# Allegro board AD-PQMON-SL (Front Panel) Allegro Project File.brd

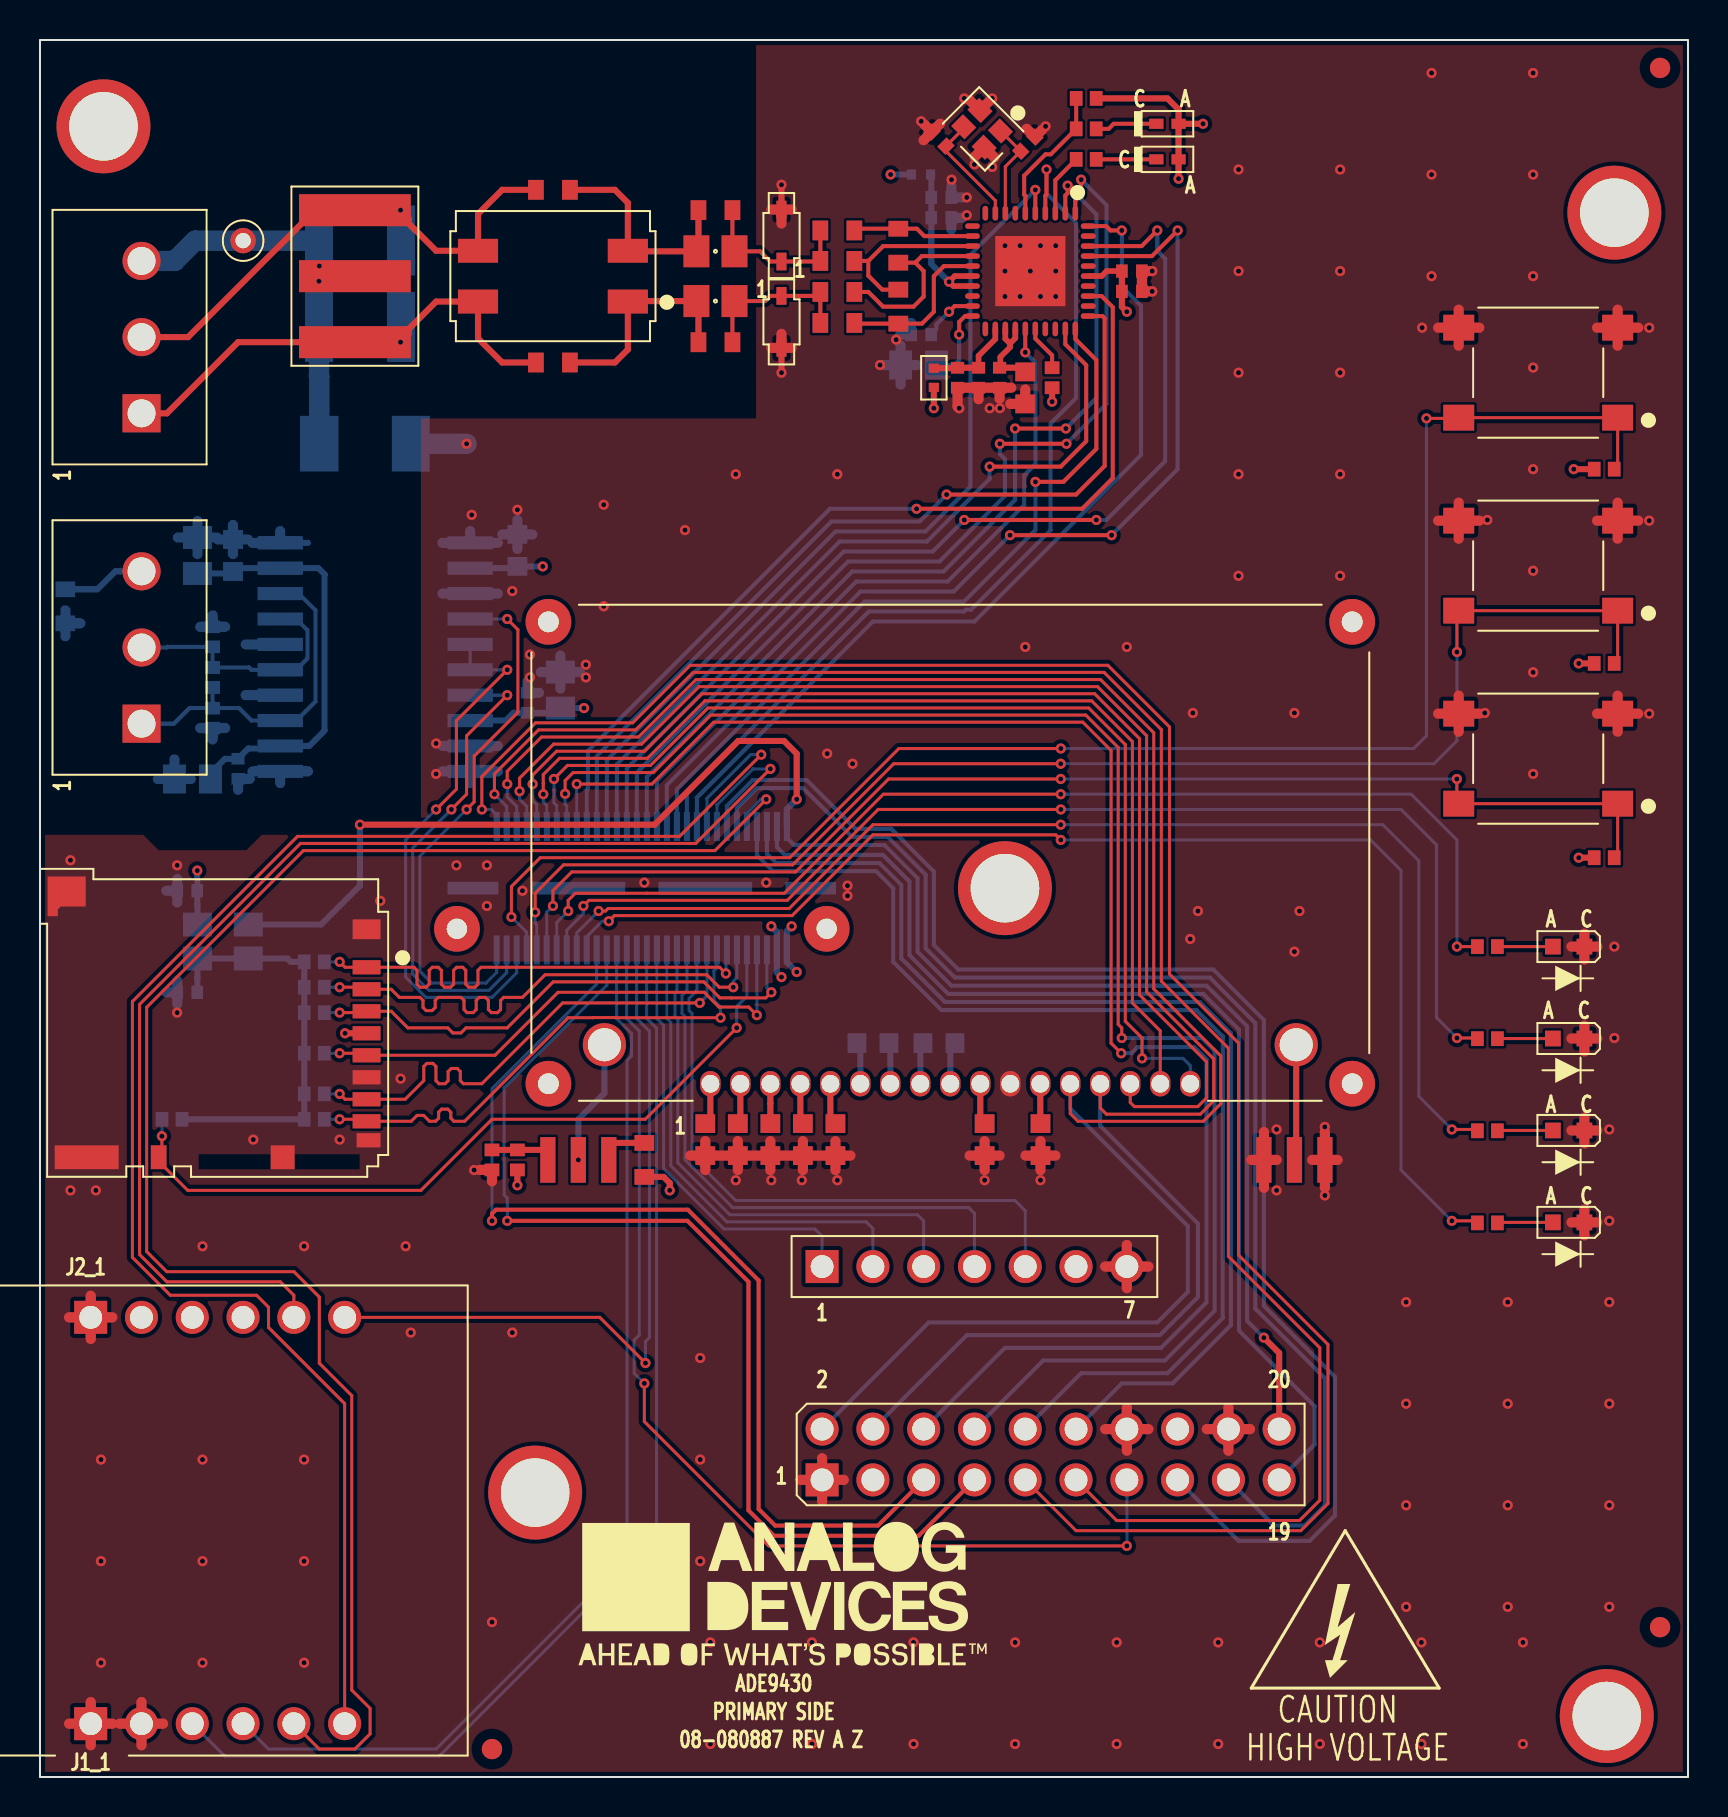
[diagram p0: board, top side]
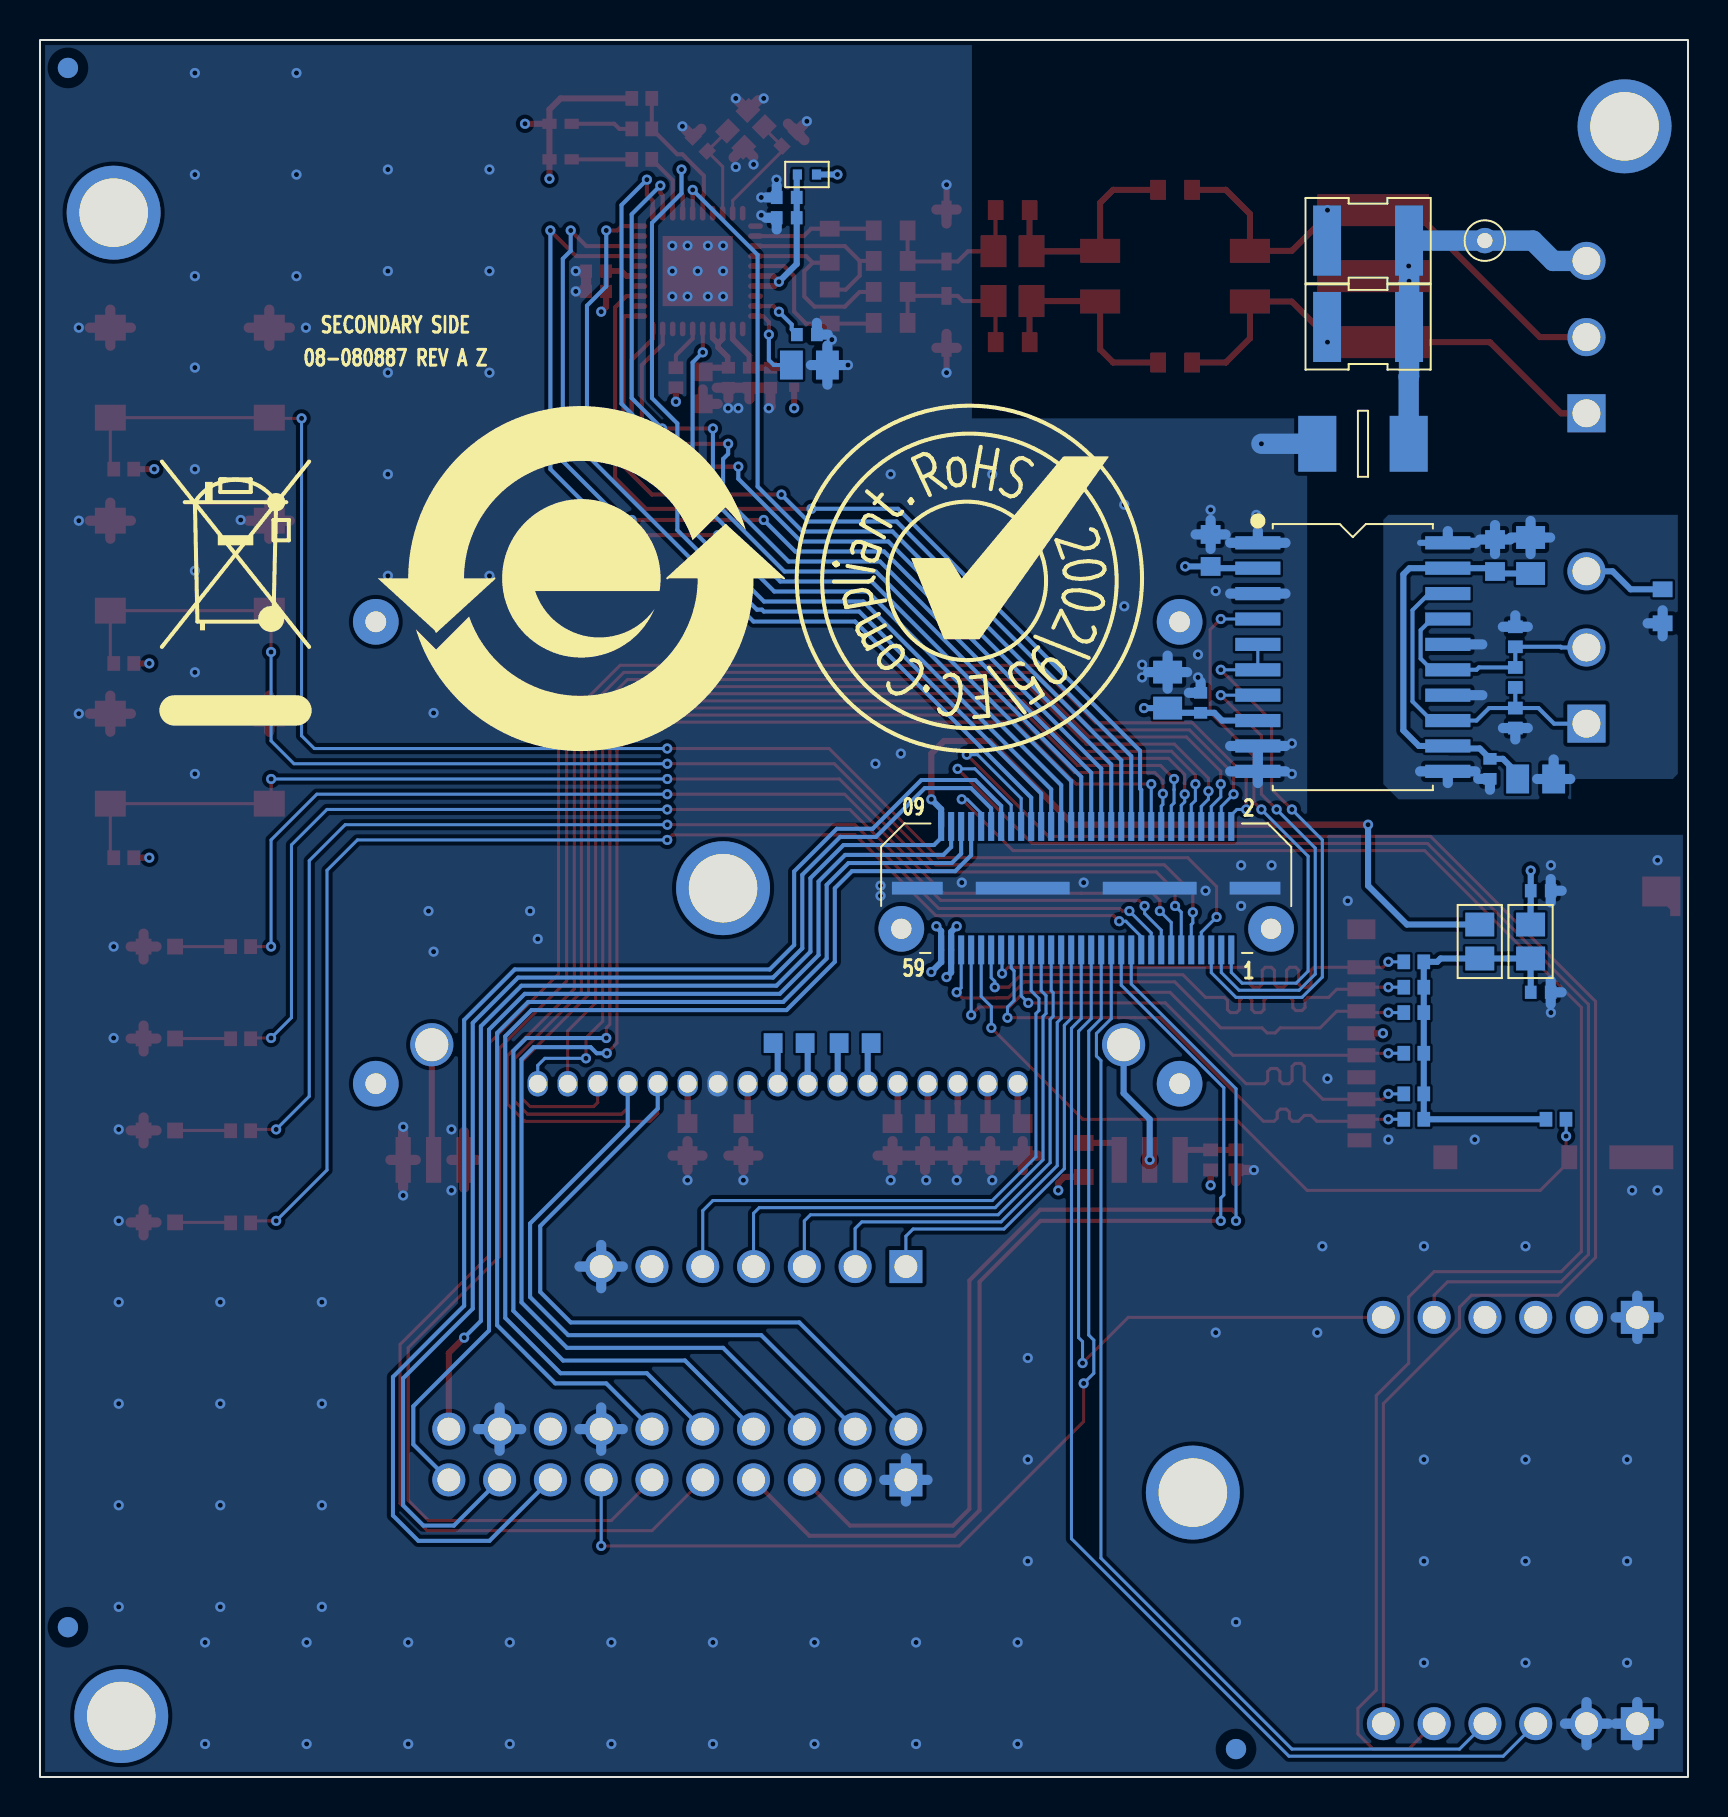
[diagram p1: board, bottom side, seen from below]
Outline 82.42 x 86.87 mm; copper layers: TOP, L2_GND, L3_PWR, BOTTOM. Coordinates in mm from the lower left corner of the outline.
Outline path: rectangle 0,0 82.42,86.87

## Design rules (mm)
constraint set DEFAULT: min track width 0.152

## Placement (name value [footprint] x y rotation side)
C1  1UF  [C0603]  33.27 31.88 270 top
C2  1UF  [C0603]  34.9 31.88 270 top
C3  0.1uF  [C0805]  7.87 61.09 270 bottom
C4  10uF  [C0603]  9.65 61.09 90 bottom
C5  10uF  [C0603]  23.88 61.34 90 bottom
C6  0.1uF  [C0805]  26.03 54.36 270 bottom
C7  0.01uF  [C0402]  24.38 53.72 90 bottom
C8  0.1uF  [C0805]  7.62 49.91 0 bottom
C9  0.01uF  [C0402]  9.91 50.42 270 bottom
C10  0.1UF  [C0402]  7.37 39.24 180 bottom
C11  0.1UF  [C0402]  7.37 44.32 180 bottom
C32  1UF  [C0603]  47.24 31.88 270 top
C33  1UF  [C0603]  44.96 36.7 0 bottom
C34  1UF  [C0603]  41.66 36.7 0 bottom
C35  0.1uF  [C0603]  50.04 31.88 270 top
C45  0.22uF  [C0805H60]  33.78 73.81 180 top
C46  0.22uF  [C0805H60]  33.78 76.3 180 top
C50  15pF  [C0402]  49.4 81.66 45 top
C51  15pF  [C0402]  44.96 81.92 135 top
C52  0.1UF  [C0402]  44.07 72.14 180 bottom
C53  1UF  [C0805H55]  43.94 70.61 180 bottom
C54  0.01uF  [C0402]  45.08 77.98 180 bottom
C55  0.01uF  [C0402]  45.89 69.98 90 top
C56  0.1UF  [C0402]  45.08 78.99 0 bottom
C57  0.1UF  [C0402]  46.94 69.98 270 top
C58  0.68uF  [C0603]  49.28 69.47 270 top
C59  0.01uF  [C0402]  54.61 75.31 0 top
C60  0.1UF  [C0402]  47.99 69.98 90 top
C61  0.1UF  [C0402]  54.61 74.3 180 top
C101  1UF  [C0603]  36.53 31.88 270 top
C105  1UF  [C0603]  38.16 31.88 270 top
C106  1UF  [C0603]  39.78 31.88 270 top
C113  100pF  [C1812H71]  16 76.84 180 bottom
C143  100pF  [C1812H71]  16 72.52 180 bottom
D5  SP4020-01FTG  [SOD323_B]  37.08 72.77 270 top
D6  2038-80-SM-RPLF  [D2038]  15.75 75.06 90 top
D19  SP4020-01FTG  [SOD323_B]  37.08 77.09 90 top
DS1  LG L29K-G2J1-24-Z  [LED0603-2]  76.45 32.33 180 top
DS2  LG L29K-G2J1-24-Z  [LED0603-2]  76.45 27.74 180 top
DS3  LG L29K-G2J1-24-Z  [LED0603-2]  76.45 41.53 180 top
DS4  LG L29K-G2J1-24-Z  [LED0603-2]  76.45 36.93 180 top
DS10  APHHS1005CGCK  [LED0402_A]  56.39 80.9 0 top
DS11  APHHS1005LSYCK/J3-PF  [LED0402H24]  56.39 82.68 0 top
E1  100OHM AT 100MEGHZ  [L0402-3]  44.06 80.14 0 bottom
E2  100OHM AT 100MEGHZ  [L0402-3]  44.7 69.98 90 top
E3  1500OHMS AT 100MEGHZ  [L0805H43]  10.41 41.78 90 bottom
E4  1500OHMS AT 100MEGHZ  [L0805H43]  7.87 41.78 90 bottom
JP3  3PIN_SMD_SOLDER_JUMPER  [JPR3P_0508]  26.92 30.86 0 top
JP4  3PIN_SMD_SOLDER_JUMPER  [JPR3P_0508]  62.74 30.86 0 top
L1  470UH  [LSML236W362H209]  25.65 75.06 90 top
M1  WIZ850IO  [MWIZ850]  8.64 12.83 0 top
NOREF  -  []  0 0 0 top
NOREF#2  -  []  42.55 103.89 270 top
NOREF#3  -  []  46.8 83.52 0 top
NOREF#4  -  [unnamed#2]  78.74 78.23 0 top
NOREF#5  -  []  48.01 201.42 0 top
NOREF#6  -  []  0 0 0 top
NOREF#7  -  [unnamed#2]  81.03 7.49 0 top
NOREF#8  -  []  0 86.87 0 top
NOREF#9  -  []  82.42 0 0 top
NOREF#10  -  []  0 86.87 270 top
NOREF#11  -  []  -49.57 191.71 0 top
NOREF#12  -  []  234.72 195.62 0 top
NOREF#13  -  [unnamed#2]  24.77 14.22 0 top
NOREF#14  -  []  0 86.87 0 top
NOREF#15  -  []  0 0 0 top
NOREF#16  -  [unnamed#2]  22.61 1.4 0 top
NOREF#17  -  []  -235.71 -165.23 0 top
NOREF#18  -  []  40.39 196.34 0 top
NOREF#19  -  []  82.42 86.87 180 top
NOREF#20  -  []  117.98 344.68 0 top
NOREF#21  -  []  82.42 0 90 top
NOREF#22  -  []  -235.71 -165.23 0 top
NOREF#23  -  []  46.98 83.7 0 top
NOREF#24  -  []  46.97 83.69 0 top
NOREF#25  -  [unnamed#2]  78.36 3.05 0 top
NOREF#26  -  []  -235.71 -165.23 0 top
NOREF#27  -  []  23 78.06 0 top
NOREF#28  -  [unnamed#2]  3.17 82.55 0 top
NOREF#29  -  []  65.02 7.24 0 top
NOREF#30  -  [unnamed#2]  81.03 85.47 0 top
NOREF#31  -  []  -69.98 193.17 0 top
NOREF#32  -  []  2.54 2.67 0 top
NOREF#33  -  []  253.36 207.01 0 top
NOREF#34  -  [unnamed#2]  48.26 44.45 0 top
NOREF#35  -  []  36.96 8.76 0 top
NOREF#36  -  []  42.03 128.52 0 top
NOREF#37  -  []  2.54 2.67 0 top
NOREF#38  -  []  82.42 0 90 top
NOREF#39  -  []  46.99 83.95 0 top
NOREF#40  -  []  55.37 59.94 180 bottom
NOREF#41  -  [unnamed#2]  81.03 7.49 180 bottom
NOREF#42  -  [unnamed#2]  22.61 1.4 180 bottom
NOREF#43  -  []  63.37 69.47 180 bottom
NOREF#44  -  []  35.94 59.82 180 bottom
NOREF#45  -  [unnamed#2]  81.03 85.47 180 bottom
P1  QTH-030-07-L-D-A  [CNSAMTECQTH-030-07-X-D-A]  30.1 44.45 0 bottom
P3  TBP02R2-381-03BE  [CNCUITBP02R2-381-03]  5.08 68.2 90 top
P4  DM3BT-DSF-PEJS  [CNHRSDM3BT-DSF-PEJS]  8.64 37.72 270 top
P5  TBP02R2-381-03BE  [CNCUITBP02R2-381-03]  5.08 52.68 90 top
P6  TSW-107-14-G-S  [CNTHMHDR1X7L700W100H433]  46.74 25.53 0 top
P7  TSW-110-08-G-D  [CNBERG2X10H330LD36]  39.12 14.86 0 top
R1  10K  [R0402]  78.23 65.41 0 top
R2  10K  [R0402]  78.23 55.69 0 top
R3  100  [R0603]  1.27 58.55 270 bottom
R4  866  [R0402]  72.39 41.53 0 top
R5  10K  [R0402]  78.23 45.97 0 top
R6  866  [R0402]  72.39 36.92 0 top
R8  866  [R0402]  72.39 32.32 0 top
R9  866  [R0402]  72.39 27.71 0 top
R12  4.7K  [R0402]  8.64 52.96 270 bottom
R13  4.7K  [R0402]  8.64 54.99 90 bottom
R15  4.7K  [R0402]  8.64 57.02 90 bottom
R16  10K  [R0402]  13.72 40.77 180 bottom
R17  5.11K  [R0603]  30.23 30.86 90 top
R18  10K  [R0402]  13.72 39.5 180 bottom
R19  10K  [R0402]  13.72 38.23 180 bottom
R20  10K  [R0402]  13.72 36.2 180 bottom
R21  10K  [R0603]  42.93 73.53 270 top
R22  49.9  [R0603]  39.88 72.72 180 top
R23  4.99K  [R0603]  39.88 75.82 180 top
R24  49.9  [R0603]  39.88 77.34 180 top
R25  4.99K  [R0603]  39.88 74.27 180 top
R26  10K  [R0603]  42.93 76.58 90 top
R27  10K  [R0402]  13.72 34.16 180 bottom
R28  10K  [R0402]  13.72 32.89 180 bottom
R29  10K  [R0402]  6.6 32.89 0 bottom
R30  8.2  [R0402]  23.88 30.86 90 top
R31  205  [R0402]  22.61 30.86 270 top
R35  1.5K  [R0402]  50.62 69.98 270 top
R36  4.7MEG  [R2010]  16.26 66.67 0 bottom
R71  1MEG  [R0603]  33.78 78.36 180 top
R72  1MEG  [R0603]  33.78 71.75 180 top
R73  10K  [R0603]  25.65 70.74 0 top
R74  10K  [R0603]  25.65 79.38 0 top
R102  4.7K  [R0402]  52.32 80.9 180 top
R104  10K  [R0402]  52.32 83.95 180 top
R105  4.7K  [R0402]  52.32 82.42 180 top
S1  PTS645SK43SMTR92LFS  [SWSMSQ236H169]  74.93 70.23 90 top
S2  PTS645SK43SMTR92LFS  [SWSMSQ236H169]  74.93 60.58 90 top
S3  PTS645SK43SMTR92LFS  [SWSMSQ236H169]  74.93 50.93 90 top
TP2  TESTPAD  [TPC50D30]  10.16 76.84 0 top
U1  NHD-C12832A1Z-NSW-BBW-3V3  [MNHD-C12832A1Z]  33.53 34.67 0 top
U2  ADM2587EBRWZ  [SO20WB-2]  16.76 56.01 270 bottom
U8  ADIN1110CCPZ  [QFN40_6X6_PAD3_5X3_5]  49.53 75.31 180 top
Y1  25MEGHZ  [YSML79W63H20]  47.12 82.42 135 top

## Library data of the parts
C1 C2 C32-C34 C101 C105 C106 = CAP: User Part Number: UPN; Tolerance: 10; alternate symbols: (C0603); part number: CAP_SM-1UF,25V,10,E048498,C0603; tolerance: 10
C3 C6 C8 = CAP: User Part Number: UPN; Tolerance: 5; alternate symbols: (C0805); part number: CAP_SM-0.1UF,50V,5,E031467,C0805; tolerance: 5
C4 C5 = CAP: User Part Number: UPN; Tolerance: 20; alternate symbols: (C0603); part number: CAP_SM-10UF,10V,20,E022682,C0603; tolerance: 20
C7 C9 C54 C55 C59 = CAP: User Part Number: UPN; Tolerance: 10; alternate symbols: (C0402); part number: CAP_SM-0.01UF,100V,10,E032295,C0402; tolerance: 10
C10 C11 C52 C56 C57 C60 C61 = CAP: User Part Number: UPN; Tolerance: 10; alternate symbols: (C0402); part number: CAP_SM-0.1UF,50V,10,E048331,C0402; tolerance: 10
C35 = CAP: User Part Number: UPN; Tolerance: 10; alternate symbols: (C0603); part number: CAP_SM-0.1UF,25V,10,E038719,C0603; tolerance: 10
C45 C46 = CAP: Tolerance: 5; User Part Number: UPN; alternate symbols: (C0805H60); part number: CAP_SM-0.22UF,100V,5,E018909,C0805H60; tolerance: 5
C50 C51 = CAP: User Part Number: UPN; Tolerance: 1; alternate symbols: (C0402); part number: CAP_SM-15PF,50V,1,E020722,C0402; tolerance: 1
C53 = CAP: User Part Number: UPN; Tolerance: 10; alternate symbols: (C0805H55); part number: CAP_SM-1UF,100V,10,E048499,C0805H55; tolerance: 10
C58 = CAP: User Part Number: UPN; Tolerance: 10; alternate symbols: (C0603); part number: CAP_SM-0.68UF,10V,10,E035107,C0603; tolerance: 10
C113 C143 = CAP: Tolerance: 5; User Part Number: UPN; alternate symbols: (C1812H71); part number: CAP_SM-100PF,3000V,5,E023439,C1812H71; tolerance: 5
D5 D19 = DIOZNR_V4: Tolerance: N/A; User Part Number: UPN; alternate symbols: (SOD323_B); part number: DIOZNR_V4_SM-SP4020-01FTG,3.3V,N/A,E028177,SOD323_B; tolerance: N/A
D6 = DIOGDT3P: User Part Number: UPN; Tolerance: N/A; alternate symbols: (D2038); part number: DIOGDT3P_SM-2038-80-SM-RPLF,800V,N/A,E048971,D2038; tolerance: N/A
DS1-DS4 = DIOLED: Tolerance: N/A; User Part Number: UPN; alternate symbols: (LED0603-2); part number: DIOLED_SM-LG L29K-G2J1-24-Z,N/A,N/A,E010948,LED0603-2; tolerance: N/A
DS10 = DIOLED: User Part Number: UPN; Tolerance: N/A; alternate symbols: (LED0402_A); part number: DIOLED_SM-APHHS1005CGCK,2.1V,N/A,E029804,LED0402_A; tolerance: N/A
DS11 = DIOLED: User Part Number: UPN; Tolerance: N/A; alternate symbols: (LED0402H24); part number: DIOLED_SM-APHHS1005LSYCK/J3-PF,1.85V,N/A,E032958,LED0402H24; tolerance: N/A
E1 E2 = FERRITE: Tolerance: 25; User Part Number: UPN; alternate symbols: (L0402-3); part number: FERRITE_SM-100OHM AT 100MEGHZ,25,E029145,L0402-3; tolerance: 25
E3 E4 = FERRITE: User Part Number: UPN; Tolerance: 25; alternate symbols: (L0805H43); part number: FERRITE_SM-1500OHMS AT 100MEGHZ,25,E028572,L0805H43; tolerance: 25
JP3 JP4 = NC3P_JMPR: User Part Number: UPN; Tolerance: N/A; alternate symbols: (JPR3P_0508); part number: NC3P_JMPR_SM-3PIN_SMD_SOLDER_JUMPER,E020448,JPR3P_0508; tolerance: N/A
L1 = CHOKE4P_V5: User Part Number: UPN; Tolerance: 50; alternate symbols: (LSML236W362H209); part number: CHOKE4P_V5_SM-470UH,50,E032119,LSML236W362H209; tolerance: 50
M1 = MOD_WIZ850: User Part Number: UPN; Tolerance: N/A; alternate symbols: (MWIZ850); part number: MOD_WIZ850_TH-WIZ850IO,E064442,MWIZ850; tolerance: N/A
P1 = CN60P_ODD_EVEN_4GND: User Part Number: UPN; Tolerance: N/A; alternate symbols: (CNSAMTECQTH-030-07-X-D-A); part number: CN60P_ODD_EVEN_4GND_SM-QTH-030-07-L-D-A,E064362,CNSAMTECQTH-030-07-X-D-A; tolerance: N/A
P3 P5 = CN3P: User Part Number: UPN; Tolerance: N/A; alternate symbols: (CNCUITBP02R2-381-03); part number: CN3P_TH-TBP02R2-381-03BE,E061218,CNCUITBP02R2-381-03; tolerance: N/A
P4 = CN10P_4PSHLD_V3: User Part Number: UPN; Tolerance: N/A; alternate symbols: (CNHRSDM3BT-DSF-PEJS); part number: CN10P_4PSHLD_V3_SM-DM3BT-DSF-PEJS,E028449,CNHRSDM3BT-DSF-PEJS; tolerance: N/A
P6 = CN7P: User Part Number: UPN; Tolerance: N/A; alternate symbols: (CNTHMHDR1X7L700W100H433); part number: CN7P_TH-TSW-107-14-G-S,E035158,CNTHMHDR1X7L700W100H433; tolerance: N/A
P7 = CN20P: Tolerance: N/A; User Part Number: UPN; alternate symbols: (CNBERG2X10H330LD36); part number: CN20P_TH-TSW-110-08-G-D,E000753,CNBERG2X10H330LD36; tolerance: N/A
R1 R2 R5 R104 = RES: User Part Number: UPN; Tolerance: 1; alternate symbols: (R0402); part number: RES_SM-10K,E003751,1/10W,1,R0402; tolerance: 1
R3 = RES: User Part Number: UPN; Tolerance: 1; alternate symbols: (R0603); part number: RES_SM-100,E003668,1/10W,1,R0603; tolerance: 1
R4 R6 R8 R9 = RES: User Part Number: UPN; Tolerance: 1; alternate symbols: (R0402); part number: RES_SM-866,E015598,1/10W,1,R0402; tolerance: 1
R12 R13 R15 = RES: User Part Number: UPN; Tolerance: 5; alternate symbols: (R0402); part number: RES_SM-4.7K,E048466,1/16W,5,R0402; tolerance: 5
R16 R18-R20 R27-R29 = RES: User Part Number: UPN; Tolerance: 1; alternate symbols: (R0402); part number: RES_SM-10K,E060779,1/16W,1,R0402; tolerance: 1
R17 = RES: User Part Number: UPN; Tolerance: 1; alternate symbols: (R0603); part number: RES_SM-5.11K,E026136,1/10W,1,R0603; tolerance: 1
R21 R26 R73 R74 = RES: User Part Number: UPN; Tolerance: 1; alternate symbols: (R0603); part number: RES_SM-10K,E003671,1/10W,1,R0603; tolerance: 1
R22 R24 = RES: User Part Number: UPN; Tolerance: 1; alternate symbols: (R0603); part number: RES_SM-49.9,E003673,1/10W,1,R0603; tolerance: 1
R23 R25 = RES: User Part Number: UPN; Tolerance: 1; alternate symbols: (R0603); part number: RES_SM-4.99K,E003726,1/10W,1,R0603; tolerance: 1
R30 = RES: User Part Number: UPN; Tolerance: 5; alternate symbols: (R0402); part number: RES_SM-8.2,E057043,1/10W,5,R0402; tolerance: 5
R31 = RES: User Part Number: UPN; Tolerance: 1; alternate symbols: (R0402); part number: RES_SM-205,E010569,1/10W,1,R0402; tolerance: 1
R35 = RES: User Part Number: UPN; Tolerance: 1; alternate symbols: (R0402); part number: RES_SM-1.5K,E003782,1/10W,1,R0402; tolerance: 1
R36 = RES: Tolerance: 5; User Part Number: UPN; alternate symbols: (R2010); part number: RES_SM-4.7MEG,E031023,1/2W,5,R2010; tolerance: 5
R71 R72 = RES: User Part Number: UPN; Tolerance: 1; alternate symbols: (R0603); part number: RES_SM-1MEG,E003682,1/10W,1,R0603; tolerance: 1
R102 R105 = RES: User Part Number: UPN; Tolerance: 5; alternate symbols: (R0402); part number: RES_SM-4.7K,E042730,1/10W,5,R0402; tolerance: 5
S1-S3 = SWSPST4PIN_B: User Part Number: UPN; Tolerance: N/A; alternate symbols: (SWSMSQ236H169); part number: SWSPST4PIN_B_SM-PTS645SK43SMTR92LFS,E019205,SWSMSQ236H169; tolerance: N/A
TP2 = NCTESTPAD: Tolerance: N/A; User Part Number: UPN; alternate symbols: (TPC50D30); part number: NCTESTPAD_TH-TESTPAD,E007450,TPC50D30; tolerance: N/A
U1 = MOD_NHD_C12832A1Z: User Part Number: UPN; Tolerance: N/A; alternate symbols: (MNHD-C12832A1Z); part number: MOD_NHD_C12832A1Z_TH-NHD-C12832A1Z-NSW-BBW-3V3,E019272,MNHD-C12832A1Z; tolerance: N/A
U2 = ADM258X: Tolerance: N/A; User Part Number: UPN; alternate symbols: (SO20WB-2); part number: ADM258X_SM-ADM2587EBRWZ,E016304,SO20WB-2; tolerance: N/A
U8 = ADIN1110_V2: User Part Number: UPN; Tolerance: N/A; alternate symbols: (QFN40_6X6_PAD3_5X3_5); part number: ADIN1110_V2_SM-ADIN1110CCPZ,E049968,QFN40_6X6_PAD3_5X3_5; tolerance: N/A
Y1 = XTAL4PIN_V3: Tolerance: 10PPM; User Part Number: UPN; alternate symbols: (YSML79W63H20); part number: XTAL4PIN_V3_SM-25MEGHZ,E051324,YSML79W63H20; tolerance: 10PPM

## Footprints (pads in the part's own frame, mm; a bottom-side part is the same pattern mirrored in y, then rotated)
C0402
  rect 0.584x0.66 smd: 1(-0.5,0) 2(0.5,0)
C0603
  rect 0.94x0.991 smd: 1(-0.8,0) 2(0.8,0)
C0805
  rect 1.143x1.448 smd: 1(-0.9,0) 2(0.9,0)
C0805H55
  rect 1.143x1.448 smd: 1(-0.9,0) 2(0.9,0)
C0805H60
  rect 1.295x1.6 smd: 1(-0.953,0) 2(0.953,0)
C1812H71
  rect 1.397x3.505 smd: 1(-2.05,0) 2(2.05,0)
CNBERG2X10H330LD36
  rect 1.651x1.651 hole 1.143: 1(0,0)
  round 1.651 hole 1.143: 2(0,2.54) 3(2.54,0) 4(2.54,2.54) 5(5.08,0) 6(5.08,2.54) 7(7.62,0) 8(7.62,2.54) 9(10.16,0) 10(10.16,2.54) 11(12.7,0) 12(12.7,2.54) 13(15.24,0) 14(15.24,2.54) 15(17.78,0) 16(17.78,2.54) 17(20.32,0) 18(20.32,2.54) 19(22.86,0) 20(22.86,2.54)
CNCUITBP02R2-381-03
  rect 1.905x1.905 hole 1.397: 1(0,0)
  round 1.905 hole 1.397: 2(3.81,0) 3(7.62,0)
CNHRSDM3BT-DSF-PEJS
  rect 0.711x1.397 smd: 1(-2.775,7.698) 2(-1.675,7.698) 3(-0.575,7.698) 4(0.525,7.698) 5(1.625,7.698) 6(2.725,7.698) 7(3.825,7.698) 8(4.925,7.698)
  rect 1.194x0.787 smd: A(6.725,-2.7)
  rect 0.711x1.194 smd: B(5.875,7.797)
  rect 0.991x1.397 smd: SH1(-4.675,7.698)
  rect 1.194x1.194 smd: SH2(6.725,3.5)
  rect 1.194x3.2 smd: SH3(6.725,-6.3)
  custom 0.476x0.476 smd: SH4(-6.325,-7.3)
CNSAMTECQTH-030-07-X-D-A
  round 2.286 hole 1.016 unplated: (-9.246,2.032) (9.246,2.032)
  rect 0.305x1.448 smd: 1(-7.257,3.086) 2(-7.257,-3.086) 3(-6.756,3.086) 4(-6.756,-3.086) 5(-6.256,3.086) 6(-6.256,-3.086) 7(-5.756,3.086) 8(-5.756,-3.086) 9(-5.255,3.086) 10(-5.255,-3.086) 11(-4.755,3.086) 12(-4.755,-3.086) 13(-4.255,3.086) 14(-4.255,-3.086) 15(-3.754,3.086) 16(-3.754,-3.086) 17(-3.254,3.086) 18(-3.254,-3.086) 19(-2.753,3.086) 20(-2.753,-3.086) 21(-2.253,3.086) 22(-2.253,-3.086) 23(-1.753,3.086) 24(-1.753,-3.086) 25(-1.252,3.086) 26(-1.252,-3.086) 27(-0.752,3.086) 28(-0.752,-3.086) 29(-0.251,3.086) 30(-0.251,-3.086) 31(0.249,3.086) 32(0.249,-3.086) 33(0.749,3.086) 34(0.749,-3.086) 35(1.25,3.086) 36(1.25,-3.086) 37(1.75,3.086) 38(1.75,-3.086) 39(2.25,3.086) 40(2.25,-3.086) 41(2.751,3.086) 42(2.751,-3.086) 43(3.251,3.086) 44(3.251,-3.086) 45(3.752,3.086) 46(3.752,-3.086) 47(4.252,3.086) 48(4.252,-3.086) 49(4.752,3.086) 50(4.752,-3.086) 51(5.253,3.086) 52(5.253,-3.086) 53(5.753,3.086) 54(5.753,-3.086) 55(6.253,3.086) 56(6.253,-3.086) 57(6.754,3.086) 58(6.754,-3.086) 59(7.254,3.086) 60(7.254,-3.086)
  rect 2.54x0.635 smd: PAD1(-8.445,0) PAD4(8.445,0)
  rect 4.699x0.635 smd: PAD2(-3.175,0) PAD3(3.175,0)
CNTHMHDR1X7L700W100H433
  rect 1.651x1.651 hole 1.143: 1(-7.62,0)
  round 1.651 hole 1.143: 2(-5.08,0) 3(-2.54,0) 4(0,0) 5(2.54,0) 6(5.08,0) 7(7.62,0)
D2038
  rect 1.6x5.588 smd: 1(-3.3,0) 2(3.3,0) 3(0,0)
JPR3P_0508
  rect 0.762x2.286 smd: 1(-1.524,0) 2(0,0) 3(1.524,0)
L0402-3
  rect 0.457x0.508 smd: 1(-0.479,0) 2(0.479,0)
L0805H43
  rect 1.194x1.448 smd: 1(-0.85,0) 2(0.85,0)
LED0402_A
  rect 0.711x0.508 smd: A(0.555,0) C(-0.555,0)
LED0402H24
  rect 0.711x0.508 smd: A(0.555,0) C(-0.555,0)
LED0603-2
  rect 0.787x0.787 smd: A(0.787,0) C(-0.787,0)
LSML236W362H209
  rect 1.194x2.007 smd: 1(-1.27,-3.747) 2(1.27,-3.747) 3(1.27,3.747) 4(-1.27,3.747)
MNHD-C12832A1Z
  round 2.286 hole 1.041 unplated: (-8.1,23.1) (-8.1,0) (32.1,23.1) (32.1,0)
  oval 1.016x1.27 hole 0.889: 1(0,0) 2(1.5,0) 3(3,0) 4(4.5,0) 5(6,0) 6(7.5,0) 7(9,0) 8(10.5,0) 9(12,0) 10(13.5,0) 11(15,0) 12(16.5,0) 13(18,0) 14(19.5,0) 15(21,0) 16(22.5,0) 17(24,0)
  round 2.159 hole 1.651: A(-5.3,1.95) K(29.3,1.95)
MWIZ850
  rect 1.651x1.651 hole 1.143: J1_1(-6.1,-10.16) J2_1(-6.1,10.16)
  round 1.651 hole 1.143: J1_2(-3.56,-10.16) J1_3(-1.02,-10.16) J1_4(1.52,-10.16) J1_5(4.06,-10.16) J1_6(6.6,-10.16) J2_2(-3.56,10.16) J2_3(-1.02,10.16) J2_4(1.52,10.16) J2_5(4.06,10.16) J2_6(6.6,10.16)
QFN40_6X6_PAD3_5X3_5
  oval 0.279x0.737 smd: 1(-2.25,-2.893) 2(-1.75,-2.893) 3(-1.25,-2.893) 4(-0.75,-2.893) 5(-0.25,-2.893) 6(0.25,-2.893) 7(0.75,-2.893) 8(1.25,-2.893) 9(1.75,-2.893) 10(2.25,-2.893) 21(2.25,2.893) 22(1.75,2.893) 23(1.25,2.893) 24(0.75,2.893) 25(0.25,2.893) 26(-0.25,2.893) 27(-0.75,2.893) 28(-1.25,2.893) 29(-1.75,2.893) 30(-2.25,2.893)
  oval 0.737x0.279 smd: 11(2.893,-2.25) 12(2.893,-1.75) 13(2.893,-1.25) 14(2.893,-0.75) 15(2.893,-0.25) 16(2.893,0.25) 17(2.893,0.75) 18(2.893,1.25) 19(2.893,1.75) 20(2.893,2.25) 31(-2.893,2.25) 32(-2.893,1.75) 33(-2.893,1.25) 34(-2.893,0.75) 35(-2.893,0.25) 36(-2.893,-0.25) 37(-2.893,-0.75) 38(-2.893,-1.25) 39(-2.893,-1.75) 40(-2.893,-2.25)
  rect 3.505x3.505 smd: PAD(0,0)
R0402
  rect 0.635x0.737 smd: 1(-0.5,0) 2(0.5,0)
R0603
  rect 0.787x0.991 smd: 1(-0.85,0) 2(0.85,0)
R2010
  rect 1.905x2.794 smd: 1(-2.286,0) 2(2.286,0)
SO20WB-2
  rect 0.66x2.261 smd: 1(-5.715,-4.75) 2(-4.445,-4.75) 3(-3.175,-4.75) 4(-1.905,-4.75) 5(-0.635,-4.75) 6(0.635,-4.75) 7(1.905,-4.75) 8(3.175,-4.75) 9(4.445,-4.75) 10(5.715,-4.75) 11(5.715,4.75) 12(4.445,4.75) 13(3.175,4.75) 14(1.905,4.75) 15(0.635,4.75) 16(-0.635,4.75) 17(-1.905,4.75) 18(-3.175,4.75) 19(-4.445,4.75) 20(-5.715,4.75)
SOD323_B
  rect 0.889x0.508 smd: 1(-1.3,0) 2(1.3,0)
SWSMSQ236H169
  rect 1.295x1.549 smd: 1(-2.25,-3.975) 2(-2.25,3.975) 3(2.25,-3.975) 4(2.25,3.975)
TPC50D30
  round 1.27 hole 0.762: 1(0,0)
unnamed#2
  round 4.699 hole 3.429 unplated: (0,0)
YSML79W63H20
  rect 0.94x0.838 smd: 1(-0.725,-0.575) 2(0.725,-0.575) 3(0.725,0.575) 4(-0.725,0.575)

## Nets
1V8: E3.2(N2) P1.60 P7.20
3V3: C5.1 C6.2(N2) C7.1 C11.1 C35.1 C59.1 C61.2(N2) DS10.A(P) DS11.A(P) E1.1 E2.1 E4.2(N2) M1.J2_2 M1.J2_3 P1.57 P1.59 P4.4 P6.6 P7.3 P7.16 R1.1 R2.1 R5.1 R17.1 R30.1 R35.2(N2) R104.1 U1.12 U2.2 U2.8 U8.35
AGND1: C3.1 C4.2(N2) C8.1 C9.2(N2) R3.2(N2) R12.2(N2) R15.2(N2) U2.11 U2.14 U2.16 U2.20
AVDD_H: C54.2(N2) C56.1 E1.2(N2) U8.16 U8.17
AVDD_L: C55.2(N2) C57.1 E2.2(N2) U8.22
DGND: C1.2(N2) C2.2(N2) C5.2(N2) C6.1 C7.2(N2) C10.2(N2) C11.2(N2) C32.2(N2) C35.2(N2) C50.2(N2) C51.2(N2) C52.2(N2) C53.2(N2) C54.1 C55.1 C56.2(N2) C57.2(N2) C58.2(N2) C59.2(N2) C60.1 C61.1 C101.2(N2) C105.2(N2) C106.2(N2) D5.2(N2) D19.2(N2) DS1.C DS2.C DS3.C DS4.C JP4.1 JP4.3 M1.J1_1 M1.J1_2 M1.J2_1 P1.PAD1 P1.PAD2 P1.PAD3 P1.PAD4 P4.6 P4.B P4.SH1 P4.SH2 P4.SH3 P4.SH4 P6.7(N7) P7.1 P7.14 P7.18 R31.2(N2) R36.2(N2) S1.3 S1.4(N4) S2.3 S2.4(N4) S3.3 S3.4(N4) U1.11(VSS) U2.1 U2.3 U2.9 U2.10 U8.PAD Y1.2 Y1.4
GND_EARTH: C113.2(N2) C143.2(N2) D6.3(E_3) P3.3(N3) R36.1 TP2.1(N1)
ADIN1110_RESET: P1.24 U8.5
AY_485: P5.1 R12.1 R13.1 U2.13 U2.18
BTN_0: P1.7 R1.2(N2) S1.1 S1.2
BTN_1: P1.9 R2.2(N2) S2.1 S2.2
BTN_2: P1.11 R5.2(N2) S3.1 S3.2
BTN_3: P1.13 R4.1
BTN_4: P1.15 R6.1
BZ_485: P5.2 R13.2(N2) R15.1 U2.15(Z) U2.17
CABLE+: C143.1 D6.1 L1.4(N4) P3.1 R73.1
CABLE-: C113.1 D6.2 L1.3 P3.2 R74.1
DATA_AND_POWER_N: C46.2(N2) L1.2 R71.2(N2) R74.2(N2)
DATA_AND_POWER_P: C45.2(N2) L1.1 R72.2(N2) R73.2(N2)
DATA_N: C46.1 D19.1 R23.2(N2) R24.2(N2) R71.1
DATA_P: C45.1 D5.1 R22.2(N2) R25.2(N2) R72.1
DLDO_1P1: C58.1 C60.2(N2) U8.23 U8.24
INT: P1.34 U8.25
LCD_A0: P1.10 U1.15
LCD_BACKLIGHT_LED+: JP3.1 R30.2(N2) R31.1
LCD_CSB: P1.14 U1.17
LCD_RST: P1.12 U1.16
LED_0: P1.17 R8.1
LED_1: P1.19 R9.1
LINK_ST: P1.40 U8.4
NR_D_485: P1.5 U2.5 U2.6
RXD_485: P1.1 U2.4
RXEV: P1.54 P7.10
RXN: R21.1 R23.1 U8.13
RXP: R25.1 R26.1 U8.14
SCL_0: P1.21 P7.5
SDA_0: P1.23 P7.7
SDIO_DAT0: P1.43 P4.7 R27.1
SDIO_DAT1: P1.45 P4.8 R28.1
SDIO_DAT2: P1.47 P4.1 R16.1
SDIO_DAT3: P1.49 P4.2 R18.1
SDIO_SOM_CD: P1.51 P4.A R29.1
SDIO_SOM_CLK: P1.53 P4.5 R20.1
SDIO_SOM_CMD: P1.55 P4.3 R19.1
SPI0_MISO: P1.16 P7.8
SPI0_MOSI: P1.6 P7.2 U1.13
SPI0_SCK: P1.8 P7.4 U1.14
SPI0_SS0: P1.18(N9) P7.6
SPI2_MISO__SPI_CFG1: P1.32 U8.2
SPI2_MOSI: P1.30 U8.1
SPI2_SCK: P1.28 U8.38
SPI2_SS0: P1.26 U8.29
SPI3_MISO: M1.J2_6 P1.29
SPI3_MOSI: M1.J1_3 P1.31
SPI3_SCK: M1.J1_4 P1.25
SPI3_SDIO2: P1.50 P7.17
SPI3_SDIO3: P1.48 P7.15
SPI3_SS0: M1.J1_5(SCN_N) P1.52
SPI3_SS1: M1.J1_6 P1.44
SPI3_SS2: M1.J2_5 P1.46
SPI3_SS3: P1.27 P7.13
SPI_CFG1: P1.36 U8.37
SPIXR_SCK: P1.2 P7.9(N9)
SPIXR_SDIO0: P1.4 P7.11
SPIXR_SDIO1: P1.58 P7.19
SWPD_EN: P1.20 U8.33
TS_CAPT: P1.42 U8.40
TS_TIMER__MS_SEL: P1.38 U8.30
TX2P4_EN: P1.22 U8.31
TXD_485: P1.3 U2.7
TXEV: P1.56 P7.12
TXN: R24.1 R26.2(N2) U8.12
TXP: R21.2(N2) R22.1 U8.15
UART2_CTS: P1.33 P6.1
UART2_PPS: P1.41 P6.5
UART2_RTS: P1.35 P6.2
UART2_RX: P1.37 P6.3
UART2_TX: P1.39 P6.4
UNNAMED_4_CN3P_I274_N3: P5.3(N3) R3.1
UNNAMED_4_DIOLED_I203_P: DS1.A(P) R8.2(N2)
UNNAMED_4_DIOLED_I206_P: DS2.A(P) R9.2(N2)
UNNAMED_4_DIOLED_I281_P: DS4.A(P) R6.2(N2)
UNNAMED_4_DIOLED_I283_P: DS3.A(P) R4.2(N2)
UNNAMED_9_ADIN1110V2_I109_CEXT2: C52.1 U8.19
UNNAMED_9_ADIN1110V2_I109_CEXT3: C53.1 U8.20
UNNAMED_9_ADIN1110V2_I109_LED0: R102.2(N2) U8.3
UNNAMED_9_ADIN1110V2_I109_LED1: R104.2(N2) R105.2(N2) U8.6
UNNAMED_9_ADIN1110V2_I109_TEST1: R35.1 U8.26
UNNAMED_9_CAP_I111_N1: C33.1 U1.8
UNNAMED_9_CAP_I111_N2: C33.2(N2) U1.9
UNNAMED_9_CAP_I113_N1: C32.1 U1.10
UNNAMED_9_CAP_I115_N1: C1.1 U1.1
UNNAMED_9_CAP_I116_N1: C34.1 U1.6
UNNAMED_9_CAP_I116_N2: C34.2(N2) U1.7
UNNAMED_9_CAP_I118_N1: C2.1 U1.2
UNNAMED_9_CAP_I120_N1: C101.1 U1.3
UNNAMED_9_CAP_I122_N1: C105.1 U1.4
UNNAMED_9_CAP_I124_N1: C106.1 U1.5
UNNAMED_9_DIOLED_I33_N: DS10.C R102.1
UNNAMED_9_DIOLED_I42_N: DS11.C R105.1
UNNAMED_9_FERRITE_I154_N1: C10.1 E3.1 E4.1 R16.2(N2) R18.2(N2) R19.2(N2) R20.2(N2) R27.2(N2) R28.2(N2) R29.2(N2)
UNNAMED_9_MODNHDC12832A1Z_I128_LED: JP4.2(COM) U1.K
UNNAMED_9_MODNHDC12832A1Z_I128_LED_1: JP3.2(COM) U1.A
UNNAMED_9_NC3PJMPR_I132_B: JP3.3 R17.2(N2)
VISOIN: C3.2(N2) C4.1 C8.2(N2) C9.1 U2.12 U2.19
XTAL_I: C50.1 U8.8 Y1.1
XTAL_O: C51.1 U8.9(XTAL_O) Y1.3(N2)

Pads without a net: M1 J2_4; U8 7 10 11 18 21 27 28 32 34 36 39

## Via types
v1: diameter 0.508, hole 0.254, TOP to BOTTOM, 272 vias

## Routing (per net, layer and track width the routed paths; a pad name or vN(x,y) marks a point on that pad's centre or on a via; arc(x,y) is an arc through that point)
1V8: length 87.6
  TOP w0.305: v1(61.21,21.97) 61.98,21.2 P7.20 ; v1(37.85,48.9) 37.85,51.18 37.21,51.81 34.92,51.81 30.73,47.62 v1(16,47.62)
  BOTTOM w0.203: v1(61.21,21.97) 60.37,22.81 60.37,37.54 58.34,39.57 45.59,39.57 43.89,41.27 43.89,44.95 42.23,46.61 37.71,46.61 37.35,46.96 P1.60
  BOTTOM w0.305: v1(37.85,48.9) 37.35,48.4 P1.60 ; v1(16,47.62) 16,44.58 14.06,42.63 E3.2
3V3: length 58.9
  TOP w0.279: C59.1 53.35,75.31 53.1,75.06 U8.35
  TOP w0.305: E2.1 v1(44.7,68.45) ; P4.4 v1(15.26,37.19) ; v1(31.5,29.34) 31.5,29.71 31.19,30.01 R17.1 ; R104.1 56.39,83.95 56.94,83.39 DS11.A ; R2.1 v1(76.96,55.69) ; R35.2 v1(50.62,68.78) ; v1(56.94,79.93) DS10.A DS11.A ; DS11.A v1(58.17,82.68) ; C59.1 C61.2 54.11,73.53 v1(54.36,73.28) ; U1.12 50.03,32.69 C35.1 ; R30.1 v1(23.88,29.59) ; R5.1 v1(76.96,45.97) ; R1.1 v1(76.71,65.41)
  L3_PWR w0.508: P6.6 51.82,26.61 ; P6.6 50.74,25.53 ; P6.6 51.82,24.45 ; P6.6 52.9,25.53 ; 7.62,21.91 M1.J2_3 ; M1.J2_3 8.7,22.99 ; M1.J2_3 7.62,24.07 ; M1.J2_3 6.54,22.99 ; 5.08,21.91 M1.J2_2 ; M1.J2_2 4,22.99 ; M1.J2_2 6.16,22.99 ; M1.J2_2 5.08,24.07 ; P7.3 42.74,14.86 ; P7.3 40.58,14.86 ; P7.3 41.66,13.78 ; P7.3 41.66,15.94
  BOTTOM w0.305: v1(36.58,42.55) 36.85,42.27 P1.57 36.85,40.24 v1(37.08,40.01) ; v1(37.59,42.55) 37.35,42.31 P1.59 37.35,40.75 v1(37.85,40.26) ; v1(25.15,60.54) C5.1 23.79,60.45 21.51,60.45 ; E4.2 7.87,43.63 7.87,43.64 C11.1 v1(7.87,45.33) ; 21.51,52.83 23.3,52.83 23.69,53.22 C7.1 25.79,53.22 C6.2 v1(27.21,53.46) ; E1.1 v1(42.54,80.14)
AGND1: length 26.2
  BOTTOM w0.305: U2.20 13.4,61.72
  BOTTOM w0.508: 8.9,61.89 C4.2 ; C4.2 9.65,61.16 ; C4.2 9.65,62.61 ; C4.2 10.4,61.89 ; R15.2 9.26,57.52 ; R15.2 8.64,58.1 ; R15.2 8.01,57.52 ; R12.2 9.26,52.46 ; R12.2 8.64,51.89 ; R12.2 8.01,52.46 ; C8.1 7.55,49.91 ; C8.1 5.89,49.91 ; C8.1 6.72,50.89 ; U2.11 13.4,50.29 ; U2.11 10.63,50.29 ; U2.11 12.01,49.71 ; 10.49,49.92 C9.2 9.91,49.37 ; 12.01,62.31 U2.20 10.63,61.72 ; 1.27,57.05 R3.2 ; R3.2 1.27,58.35 ; R3.2 2.02,57.7 ; U2.14 10.28,54.1 ; C3.1 8.85,61.99 ; C3.1 6.9,61.99 ; C3.1 7.87,62.81 ; C3.1 7.87,61.16 ; U2.16 10.29,56.64
AVDD_H: length 8.3
  TOP w0.279: U8.17 45.68,74.56 v1(45.47,74.78) 45.75,75.06 U8.16
  BOTTOM w0.305: v1(45.47,74.78) 44.58,75.67 C54.2 C56.1 44.58,80.11 E1.2
AVDD_L: length 4.5
  TOP w0.279: C57.1 46.94,71.07 47.78,71.91 U8.22
  TOP w0.305: E2.2 45.87,70.46 C55.2 C57.1
DGND: length 208.5
  TOP w0.254: 37.08,70.99 D5.2
  TOP w0.305: v1(37.08,70.23) 37.08,70.99 ; v1(37.08,79.63) D19.2
  TOP w0.508: C32.2 47.24,31.8 ; C32.2 47.99,31.08 ; C32.2 47.24,30.35 ; C32.2 46.49,31.08 ; P7.18 59.44,18.48 ; P7.18 59.44,16.32 ; P7.18 60.52,17.4 ; P7.18 58.36,17.4 ; 61.21,29.46 JP4.1 ; JP4.1 60.58,30.86 ; JP4.1 61.21,32.26 ; JP4.1 61.85,30.86 ; 47.49,83.82 Y1.2 46.5,83.85 ; 5.08,1.59 M1.J1_2 ; M1.J1_2 5.08,3.75 ; M1.J1_2 6.16,2.67 ; M1.J1_2 4,2.67 ; M1.J1_1 3.62,2.67 ; M1.J1_1 2.54,3.75 ; M1.J1_1 2.54,1.59 ; M1.J1_1 1.46,2.67 ; 77.24,36.28 DS4.C ; DS4.C 77.24,37.58 ; DS4.C 77.89,36.93 ; DS4.C 76.59,36.93 ; JP4.3 64.9,30.86 ; JP4.3 63.63,30.86 ; JP4.3 64.26,29.46 ; JP4.3 64.26,32.26 ; S2.4 71.98,62.83 ; S2.4 69.93,62.83 ; S2.4 70.96,61.93 ; S2.4 70.96,63.73 ; 35.78,31.08 C101.2 ; C101.2 36.53,31.8 ; C101.2 37.28,31.08 ; C101.2 36.53,30.35 ; C105.2 38.91,31.08 ; C105.2 38.16,30.35 ; C105.2 38.16,31.8 ; C105.2 37.41,31.08 ; 49.28,69.39 C58.2 48.53,68.67 ; P7.1 39.12,15.94 ; P7.1 40.2,14.86 ; P7.1 39.12,13.78 ; P7.1 38.04,14.86 ; S3.3 78.9,54.08 ; S3.3 77.88,53.18 ; S3.3 78.9,52.27 ; S3.3 79.93,53.18 ; D5.2 37.59,71.47 ; D5.2 36.58,71.47 ; D5.2 37.08,72.17 ; 54.36,24.45 P6.7 ; P6.7 55.44,25.53 ; P6.7 54.36,26.61 ; P6.7 53.28,25.53 ; 53.28,17.4 P7.14 ; P7.14 55.44,17.4 ; P7.14 54.36,16.32 ; P7.14 54.36,18.48 ; C57.2 C55.1 45.89,68.54 v1(45.97,68.45) ; C57.2 C60.1 ; C57.2 46.94,68.9 ; 70.96,52.27 S3.4 ; S3.4 69.93,53.18 ; S3.4 70.96,54.08 ; S3.4 71.98,53.18 ; C60.1 48.58,69.48 ; C60.1 47.99,68.93 ; C51.2 45.02,82.68 ; C51.2 44.22,82.66 ; C51.2 44.19,81.86 ; 50.14,82.4 C50.2 49.34,82.43 ; DS1.C 77.24,32.98 ; DS1.C 77.24,31.69 ; DS1.C 76.59,32.33 ; DS1.C 77.89,32.33 ; S1.4 70.96,73.38 ; S1.4 71.98,72.48 ; S1.4 69.93,72.48 ; S1.4 70.96,71.58 ; 34.15,31.08 C2.2 ; C2.2 35.65,31.08 ; C2.2 34.9,30.35 ; C2.2 34.9,31.8 ; C1.2 34.02,31.08 ; C1.2 33.27,30.35 ; C1.2 33.27,31.8 ; C1.2 32.52,31.08 ; 78.9,71.58 S1.3 ; S1.3 78.9,73.38 ; S1.3 79.93,72.48 ; S1.3 77.88,72.48 ; 46.75,81.03 47.22,81.5 47.74,80.99 ; 77.24,40.88 DS3.C ; DS3.C 77.24,42.18 ; DS3.C 76.59,41.53 ; DS3.C 77.89,41.53 ; 21.98,30.36 R31.2 22.61,29.79 ; C35.2 50.79,31.08 ; C35.2 50.04,31.8 ; C35.2 50.04,30.35 ; C35.2 49.29,31.08 ; 37.08,77.69 D19.2 ; D19.2 37.59,78.39 ; D19.2 36.58,78.39 ; C106.2 39.78,31.8 ; C106.2 39.03,31.08 ; C106.2 39.78,30.35 ; C106.2 40.53,31.08 ; DS2.C 77.89,27.74 ; DS2.C 77.24,27.09 ; DS2.C 76.59,27.74 ; DS2.C 77.24,28.39 ; S2.3 79.93,62.83 ; S2.3 78.9,61.93 ; S2.3 78.9,63.73 ; S2.3 77.88,62.83 ; 2.54,21.91 M1.J2_1 ; M1.J2_1 3.62,22.99 ; M1.J2_1 1.46,22.99 ; M1.J2_1 2.54,24.07 ; v1(55.63,74.3) C61.1 C59.2 v1(55.63,75.31)
  L2_GND w0.508: P7.18 59.44,18.48 ; P7.18 60.52,17.4 ; P7.18 58.36,17.4 ; P7.18 59.44,16.32 ; 5.08,1.59 M1.J1_2 ; M1.J1_2 4,2.67 ; M1.J1_2 6.16,2.67 ; M1.J1_2 5.08,3.75 ; P7.14 54.36,18.48 ; P7.14 55.44,17.4 ; P7.14 53.28,17.4 ; P7.14 54.36,16.32 ; P7.1 40.2,14.86 ; P7.1 38.04,14.86 ; P7.1 39.12,13.78 ; P7.1 39.12,15.94 ; P6.7 54.36,26.61 ; P6.7 53.28,25.53 ; P6.7 54.36,24.45 ; P6.7 55.44,25.53 ; M1.J2_1 2.54,24.07 ; M1.J2_1 2.54,21.91 ; M1.J2_1 1.46,22.99 ; M1.J2_1 3.62,22.99 ; 2.54,1.59 M1.J1_1 ; M1.J1_1 1.46,2.67 ; M1.J1_1 3.62,2.67 ; M1.J1_1 2.54,3.75
  BOTTOM w0.508: 54.36,16.32 P7.14 ; P7.14 55.44,17.4 ; P7.14 54.36,18.48 ; P7.14 53.28,17.4 ; 45.58,77.39 C54.1 46.12,77.98 ; M1.J1_1 3.62,2.67 ; M1.J1_1 2.54,3.75 ; M1.J1_1 2.54,1.59 ; M1.J1_1 1.46,2.67 ; C5.2 24.63,62.14 ; C5.2 23.88,61.42 ; C5.2 23.88,62.87 ; C5.2 23.13,62.14 ; 20.13,51.56 U2.9 ; U2.9 21.51,50.98 ; U2.9 22.9,51.56 ; M1.J1_2 6.16,2.67 ; M1.J1_2 4,2.67 ; M1.J1_2 5.08,3.75 ; M1.J1_2 5.08,1.59 ; 20.13,61.72 U2.1 ; U2.1 22.9,61.72 ; U2.1 21.51,62.31 ; 39.12,13.78 P7.1 ; P7.1 39.12,15.94 ; P7.1 40.2,14.86 ; P7.1 38.04,14.86 ; 45.58,79.58 C56.2 46.12,78.99 ; C6.1 27.01,55.26 ; C6.1 26.03,54.43 ; C6.1 26.03,56.08 ; C6.1 25.05,55.26 ; P6.7 55.44,25.53 ; P6.7 54.36,26.61 ; P6.7 53.28,25.53 ; P6.7 54.36,24.45 ; 21.51,49.71 U2.10 ; U2.10 20.13,50.29 ; U2.10 22.9,50.29 ; U2.10 21.51,50.88 ; P7.18 59.44,18.48 ; P7.18 59.44,16.32 ; P7.18 58.36,17.4 ; P7.18 60.52,17.4 ; 6.32,44.32 C11.2 ; C11.2 6.87,44.91 ; C11.2 6.87,43.74 ; 1.46,22.99 M1.J2_1 ; M1.J2_1 2.54,21.91 ; M1.J2_1 3.62,22.99 ; M1.J2_1 2.54,24.07 ; 6.32,39.24 C10.2 ; C10.2 6.87,38.66 ; C10.2 6.87,39.83 ; C53.2 43.04,71.59 ; C53.2 43.87,70.61 ; C53.2 43.04,69.63 ; C53.2 42.22,70.61 ; 20.13,59.18 U2.3 22.9,59.18 ; 24.96,54.22 C7.2 24.38,54.77 ; 43.57,72.72 C52.2 43.02,72.14
  BOTTOM w1.016: R36.2 v1(21.34,66.67)
  vias: v1(1.52,45.85) v1(1.52,29.34) v1(2.79,29.34) v1(3.05,15.88) v1(3.05,10.79) v1(3.05,5.71) v1(6.86,45.59) v1(6.86,38.23) v1(8.13,26.54) v1(8.13,15.88) v1(8.13,10.79) v1(8.13,5.71) v1(10.67,31.88) v1(13.21,26.54) v1(13.21,15.88) v1(13.21,10.79) v1(13.21,5.71) v1(14.99,31.88) v1(17.02,43.82) v1(18.03,34.93) v1(18.29,26.54) v1(18.54,22.23) v1(19.81,51.69) v1(19.81,50.16) v1(20.83,45.59) v1(21.59,63.12) v1(21.71,30.35) v1(22.35,45.59) v1(22.35,43.56) v1(22.61,7.75) v1(23.62,59.31) v1(23.62,22.23) v1(23.88,63.37) v1(24.13,44.32) v1(24.51,56.13) v1(24.51,54.99) v1(27.3,55.63) v1(27.3,54.99) v1(28.19,63.63) v1(28.19,58.55) v1(30.23,44.73) v1(32.26,62.36) v1(33.02,20.95) v1(33.02,15.88) v1(33.02,10.79) v1(33.53,6.73) v1(33.53,1.65) v1(34.8,65.15) v1(34.8,29.84) v1(36.32,44.73) v1(36.58,29.84) v1(38.1,29.84) v1(38.61,6.73) v1(38.61,1.65) v1(39.37,51.18) v1(39.88,65.15) v1(39.88,29.84) v1(40.39,44.58) v1(40.39,44.07) v1(40.64,50.67) v1(42.01,70.61) v1(42.82,71.88) v1(43.69,6.73) v1(43.69,1.65) v1(44.07,82.8) v1(45.59,79.88) v1(46.23,83.95) v1(46.35,78.99) v1(46.35,78.11) v1(46.74,80.64) v1(47.24,29.84) v1(47.5,68.45) v1(47.62,83.95) v1(47.62,80.52) v1(48.01,68.45) v1(48.26,76.58) v1(48.26,75.31) v1(48.26,74.04) v1(48.77,6.73) v1(48.77,1.65) v1(49.02,76.58) v1(49.02,74.04) v1(49.28,56.52) v1(49.53,75.31) v1(50.04,76.58) v1(50.04,74.04) v1(50.04,29.84) v1(50.29,82.55) v1(50.8,76.58) v1(50.8,75.31) v1(50.8,74.04) v1(53.85,6.73) v1(53.85,1.65) v1(54.36,56.52) v1(57.53,41.91) v1(57.66,53.21) v1(57.91,43.31) v1(58.93,6.73) v1(58.93,1.65) v1(59.94,80.39) v1(59.94,75.31) v1(59.94,70.23) v1(59.94,65.15) v1(59.94,60.07) v1(61.84,32.39) v1(61.84,29.34) v1(62.74,53.21) v1(62.74,41.27) v1(62.99,43.31) v1(64.01,6.73) v1(64.01,1.65) v1(64.26,32.51) v1(64.26,29.08) v1(65.02,80.39) v1(65.02,75.31) v1(65.02,70.23) v1(65.02,65.15) v1(65.02,60.07) v1(68.33,23.75) v1(68.33,18.67) v1(68.33,13.59) v1(68.33,8.51) v1(69.12,72.48) v1(69.09,6.73) v1(69.09,1.65) v1(69.6,85.22) v1(69.6,80.14) v1(69.6,75.06) v1(72.26,53.21) v1(72.39,62.87) v1(73.41,23.75) v1(73.41,18.67) v1(73.41,13.59) v1(73.41,8.51) v1(74.17,6.73) v1(74.17,1.65) v1(74.68,85.22) v1(74.68,80.14) v1(74.68,75.06) v1(74.68,70.48) v1(74.68,65.41) v1(74.68,60.33) v1(74.68,55.25) v1(74.68,50.16) v1(78.49,32.38) v1(78.49,27.81) v1(78.49,23.75) v1(78.49,18.67) v1(78.49,13.59) v1(78.49,8.51) v1(78.74,41.53) v1(78.74,36.96) v1(80.48,72.48) v1(80.48,62.83) v1(80.48,53.18)
GND_EARTH: length 19.5
  BOTTOM w1.016: R36.1 13.97,70.04 13.95,70.05 C143.2 v1(13.95,74.8) C113.2 TP2.1 7.76,76.84 6.74,75.82 P3.3
  vias: v1(13.97,75.56)
ADIN1110_RESET: length 44.5
  TOP w0.203: U8.5 v1(49.78,79.37)
  BOTTOM w0.203: v1(49.78,79.37) 46.53,76.12 46.53,64.54 44.29,62.29 39.79,62.29 28.35,50.85 P1.24
AY_485: length 17.4
  BOTTOM w0.203: P5.1 6.7,52.68 7.48,53.46 R12.1 ; R12.1 9.95,53.46 10.58,52.83 12.82,52.83 13.78,53.79 13.78,58.35 12.95,59.18 U2.18 ; R12.1 R13.1
BTN_0: length 80.5
  TOP w0.152: R1.2 78.9,65.58 S1.1 S1.2 70.92,67.95 v1(69.34,67.95) ; v1(23.58,43.01) 23.58,44.53 25.02,45.97 37.5,45.97 42.96,51.44 v1(51.05,51.44)
  BOTTOM w0.152: v1(23.58,43.01) 24.34,42.24 P1.7 ; v1(51.05,51.44) 68.7,51.44 69.34,52.07 v1(69.34,67.95)
BTN_1: length 69.3
  TOP w0.152: v1(70.87,56.26) 70.87,58.24 S2.2 S2.1 78.9,55.86 R2.2 ; v1(24.77,43.24) 24.77,44.2 26.19,45.62 37.64,45.62 42.7,50.67 v1(51.05,50.67)
  BOTTOM w0.152: P1.9 24.84,42.63 24.77,42.71 v1(24.77,43.24) ; v1(51.05,50.67) 69.72,50.67 70.87,51.82 v1(70.87,56.26)
BTN_2: length 62.6
  TOP w0.152: v1(25.65,43.56) 25.65,44.32 26.59,45.26 37.79,45.26 42.44,49.91 v1(51.05,49.91) ; R5.2 78.9,46.15 S3.1 S3.2 70.86,48.77 v1(70.86,49.91)
  BOTTOM w0.152: P1.11 25.34,43.25 v1(25.65,43.56) ; v1(70.86,49.91) v1(51.05,49.91)
BTN_3: length 56.7
  TOP w0.152: v1(26.42,43.31) 26.42,43.84 26.77,44.2 30.35,44.2 30.35,44.2 37.23,44.2 42.18,49.15 v1(51.05,49.15) ; v1(70.87,41.53) R4.1
  BOTTOM w0.152: v1(26.42,43.31) 25.84,42.74 P1.13 ; v1(70.87,41.53) 70.87,46.86 68.58,49.15 v1(51.05,49.15)
BTN_4: length 59.1
  TOP w0.152: R6.1 71.86,36.96 v1(70.87,36.96) ; v1(27.18,43.56) 27.46,43.84 37.37,43.84 41.92,48.39 v1(51.05,48.39)
  BOTTOM w0.152: v1(51.05,48.39) 68.07,48.39 69.85,46.61 69.85,37.98 v1(70.87,36.96) ; P1.15 26.34,42.35 27.18,43.18 v1(27.18,43.56)
BZ_485: length 12.6
  BOTTOM w0.203: P5.2 6.34,56.49 6.37,56.52 R15.1 R13.2 10.46,55.49 10.58,55.37 12.81,55.37 13.37,55.93 13.37,57.35 12.81,57.91 12.01,57.91
CABLE+: length 24.5
  TOP w0.203: D6.1 v1(18.03,71.76)
  TOP w0.305: v1(18.03,71.76) 18.43,72.15 18.43,72.4 19.81,73.79 L1.4 21.91,71.95 23.11,70.74 R73.1 ; P3.1 6.35,68.2 9.91,71.76 D6.1
CABLE-: length 25.7
  TOP w0.203: D6.2 v1(18.03,78.36)
  TOP w0.305: v1(18.03,78.36) 18.43,77.96 18.43,77.71 19.81,76.33 L1.3 21.91,78.17 23.11,79.38 R74.1 ; P3.2 7.41,72.01 13.75,78.36 D6.2
DATA_AND_POWER_N: length 11.1
  TOP w0.305: R74.2 28.75,79.38 29.4,78.73 L1.2 29.43,76.3 C46.2 32.93,76.4 R71.2
DATA_AND_POWER_P: length 11.1
  TOP w0.305: R72.2 32.93,73.71 C45.2 29.43,73.81 L1.1 29.4,71.39 28.75,70.74 R73.2
DATA_N: length 8.1
  TOP w0.203: R71.1 34.63,76.4 C46.1 36.01,76.3 36.53,75.79 D19.1 39,75.79 R23.2 R24.2
DATA_P: length 8.1
  TOP w0.203: R22.2 R25.2 38.83,74.07 D5.1 36.53,74.07 36.27,73.81 C45.1 34.63,73.71 R72.1
DLDO_1P1: length 4.4
  TOP w0.279: U8.23 48.28,71.92 48.51,71.69 ; U8.24 48.78,71.96 48.51,71.69 ; 48.51,71.69 48.51,71.5 48.03,71.02 48.03,70.48
  TOP w0.305: C60.2 49.07,70.48 C58.1
INT: length 35.6
  TOP w0.203: U8.25 49.28,72.41 v1(49.28,71.25)
  BOTTOM w0.203: P1.34 30.85,49.81 40.83,59.79 45.4,59.79 49.23,63.61 49.23,65.1 49.78,65.66 49.78,70.74 v1(49.28,71.25)
LCD_A0: length 60
  TOP w0.152: U1.15 54.53,33.73 54.73,33.53 57.91,33.53 58.34,33.96 58.34,35.76 54.99,39.12 54.99,51.93 52.74,54.17 33.11,54.17 30.23,51.3 25.83,51.3 24.64,50.1 v1(24.64,49.66)
  BOTTOM w0.152: P1.10 24.84,48.63 24.64,48.83 v1(24.64,49.66)
LCD_BACKLIGHT_LED+: length 3.1
  TOP w0.305: JP3.1 25.4,31.06 25.1,31.36 R30.2 R31.1
LCD_CSB: length 52.7
  TOP w0.152: v1(25.7,49.91) 26.38,50.59 30.53,50.59 33.4,53.46 52.45,53.46 54.28,51.63 54.28,37.8 55.12,36.96 v1(55.12,35.94)
  BOTTOM w0.152: v1(25.7,49.91) 25.7,49.38 25.7,49.38 25.7,48.71 25.84,48.57 P1.14 ; v1(55.12,35.94) 57.17,35.94 57.53,35.59 U1.17
LCD_RST: length 52.2
  TOP w0.152: U1.16 56.03,37.32 54.64,38.71 54.64,51.78 52.6,53.82 33.26,53.82 30.38,50.94 25.98,50.94 25.17,50.13 25.17,49.69 25.17,49.69 v1(25.17,49.15)
  BOTTOM w0.152: v1(25.17,49.15) 25.17,48.77 25.34,48.59 P1.12
LED_0: length 61.4
  TOP w0.152: v1(51.05,47.62) 41.66,47.62 37.47,43.43 28.41,43.43 28.28,43.31 v1(27.94,43.31) ; R8.1 71.82,32.38 v1(70.61,32.38)
  BOTTOM w0.152: v1(70.61,32.38) 68.96,34.04 68.96,45.83 67.16,47.62 v1(51.05,47.62) ; P1.17 26.85,42.21 v1(27.94,43.31)
LED_1: length 64.1
  TOP w0.152: v1(51.05,46.86) 50.8,47.12 41.66,47.12 37.62,43.08 28.73,43.08 v1(28.45,42.8) ; v1(70.61,27.81) 71.79,27.81 R9.1
  BOTTOM w0.152: v1(70.61,27.81) 68.07,30.36 68.07,45.34 66.55,46.86 v1(51.05,46.86) ; P1.19 27.35,42.03 28.12,42.8 v1(28.45,42.8)
LINK_ST: length 46.7
  TOP w0.203: U8.4 50.28,79.08 50.34,79.14 v1(50.34,80.39)
  BOTTOM w0.203: P1.40 32.35,49.19 41.45,58.29 46.22,58.29 46.31,58.38 46.57,58.38 50.55,62.36 50.55,67.69 51.82,68.96 51.82,77.72 50.34,79.2 v1(50.34,80.39)
NR_D_485: length 28.2
  TOP w0.152: v1(19.81,48.39) 20.83,49.4 20.83,52.83 v1(23.37,55.37)
  BOTTOM w0.152: v1(23.37,55.37) 21.51,55.37 U2.5 ; P1.5 23.84,40.23 22.61,38.99 19.3,38.99 18.29,40.01 18.29,46.86 v1(19.81,48.39)
RXD_485: length 27.2
  TOP w0.152: v1(23.37,57.91) 23.9,57.38 23.9,53.24 21.71,51.05 21.71,48.76 v1(21.34,48.39)
  BOTTOM w0.152: P1.1 22.84,40.24 22.3,39.7 19.6,39.7 19,40.3 19,46.05 v1(21.34,48.39) ; v1(23.37,57.91) 21.51,57.91
RXEV: length 56.9
  BOTTOM w0.203: P7.10 52.07,20.19 56.39,20.19 59.15,22.96 59.15,37.04 57.84,38.35 45.09,38.35 42.67,40.77 42.67,44.45 41.82,45.3 36.65,45.3 35.85,46.1 P1.54
RXN: length 8.7
  TOP w0.203: 41.43,75.82 R23.1 ; 41.43,75.82 42.17,76.56 U8.13 ; 41.43,75.82 41.43,75.08 42.13,74.38 R21.1
RXP: length 9.7
  TOP w0.203: 43.78,75.73 44.11,76.06 U8.14 ; 43.78,75.73 44.2,75.31 44.2,74.04 43.69,73.53 42.16,73.53 41.43,74.27 R25.1 ; 43.78,75.73 R26.1
SCL_0: length 51.9
  TOP w0.203: v1(22.61,27.81) 22.61,28.17 22.81,28.37 32.4,28.37 35.94,24.83 35.94,13.4 36.77,12.57 41.91,12.57 P7.5
  BOTTOM w0.152: v1(22.61,27.81) 22.61,34.42 27.85,39.66 P1.21
SDA_0: length 53.5
  TOP w0.203: v1(23.37,27.81) 32.39,27.81 35.43,24.77 35.43,13.33 36.7,12.06 43.94,12.06 P7.7
  BOTTOM w0.152: v1(23.37,27.81) 23.37,28.96 23.22,29.11 23.22,34.47 28.35,39.6 P1.23
SDIO_DAT0: length 26.5
  TOP w0.152: v1(33,38.71) 26.14,38.71 22.1,34.67 21.17,34.67 21.02,34.82 21.02,35.28 20.87,35.43 20.56,35.43 20.41,35.28 20.41,34.82 20.26,34.67 19.96,34.67 19.8,34.82 19.8,35.53 19.65,35.69 19.35,35.69 19.19,35.53 19.19,34.82 18.26,33.89 P4.7 15.25,33.89 v1(14.99,34.16)
  BOTTOM w0.152: v1(14.99,34.16) R27.1 ; v1(33,38.71) 33.35,39.07 P1.43
SDIO_DAT1: length 26.7
  TOP w0.152: v1(34.04,37.97) 28.8,37.97 28.79,37.98 27.66,37.98 27.66,37.97 26.42,37.97 21.24,32.79 20.7,32.79 20.55,32.95 20.55,33.25 20.39,33.4 20.09,33.4 19.94,33.25 19.94,32.95 19.78,32.79 19.48,32.79 19.19,33.09 18.86,33.09 18.57,32.79 P4.8 16.24,32.89 v1(14.99,32.89)
  BOTTOM w0.152: v1(34.04,37.97) 34.04,38.51 33.71,38.84 33.71,40.32 33.85,40.46 P1.45 ; v1(14.99,32.89) R28.1
SDIO_DAT2: length 26.4
  TOP w0.152: v1(14.99,40.77) 15.26,40.49 P4.1 18.7,40.49 18.86,40.34 18.86,39.65 19.01,39.5 19.31,39.5 19.47,39.65 19.47,40.34 19.62,40.49 19.92,40.49 20.08,40.34 20.08,39.65 20.23,39.5 20.53,39.5 20.69,39.65 20.69,40.34 20.84,40.49 21.14,40.49 21.29,40.34 21.29,39.65 21.45,39.5 21.75,39.5 21.9,39.65 21.9,40.34 22.06,40.49 33.99,40.49 v1(34.31,40.18)
  BOTTOM w0.152: v1(34.31,40.18) 34.31,40.19 34.31,41.32 P1.47 ; v1(14.99,40.77) R16.1
SDIO_DAT3: length 26.6
  TOP w0.152: v1(34.67,39.5) 33.97,39.5 33.35,40.12 25.26,40.12 24.13,38.99 23.19,38.99 23.04,38.84 23.04,38.38 22.88,38.23 22.58,38.23 22.43,38.38 22.43,38.84 22.27,38.99 21.97,38.99 21.82,38.84 21.82,38.38 21.66,38.23 21.36,38.23 21.21,38.38 21.21,38.84 21.05,38.99 19.92,38.99 19.77,38.84 19.77,38.48 19.61,38.33 19.31,38.33 19.16,38.48 19.16,38.84 19,38.99 17.97,38.99 17.57,39.39 P4.2 16.23,39.5 v1(14.99,39.5)
  BOTTOM w0.152: v1(34.67,39.5) 34.67,39.79 34.85,39.97 P1.49 ; v1(14.99,39.5) R18.1
SDIO_SOM_CD: length 39.2
  TOP w0.152: v1(6.1,32.05) 6.1,31.15 P4.A 5.94,30.79 7.39,29.34 19.05,29.34 22.61,32.89 30.27,32.89 v1(34.84,37.47)
  BOTTOM w0.152: P1.51 35.35,39.03 34.84,38.53 v1(34.84,37.47) ; R29.1 6.1,32.89 v1(6.1,32.05)
SDIO_SOM_CLK: length 26.7
  TOP w0.152: v1(14.99,36.2) 16.23,36.2 P4.5 22.76,36.09 25.91,39.24 32.77,39.24 32.78,39.25 33.22,39.25 33.96,38.51 35.45,38.51 v1(35.85,38.1)
  BOTTOM w0.152: P1.53 v1(35.85,38.1) ; v1(14.99,36.2) R20.1
SDIO_SOM_CMD: length 26.6
  TOP w0.152: v1(36.58,39.24) 36.3,38.96 34.58,38.96 34.58,38.96 34,38.96 33.2,39.77 25.67,39.77 23.37,37.47 21.31,37.47 21.05,37.21 20.65,37.21 20.39,37.47 18.4,37.47 17.57,38.29 P4.3 16.27,38.23 v1(14.99,38.23)
  BOTTOM w0.152: v1(36.58,39.24) 36.35,39.47 P1.55 ; v1(14.99,38.23) R19.1
SPI0_MISO: length 79
  TOP w0.152: v1(26.26,49.17) 26.26,49.83 26.67,50.23 30.67,50.23 33.55,53.11 52.3,53.11 53.92,51.49 53.92,37.64 54.1,37.46 v1(54.1,36.96)
  BOTTOM w0.152: v1(26.26,49.17) 26.26,48.64 26.34,48.56 P1.16
  BOTTOM w0.203: P7.8 50.16,20.83 56.26,20.83 58.75,23.31 58.75,36.31 58.1,36.96 v1(54.1,36.96)
SPI0_MOSI: length 101.8
  TOP w0.152: v1(23.37,49.66) 23.37,50.3 25.08,52.01 29.94,52.01 32.81,54.89 53.04,54.89 55.7,52.22 55.7,39.41 59.05,36.06 59.05,33.67 58.18,32.79 51.91,32.79 51.53,33.18 U1.13
  BOTTOM w0.152: v1(23.37,49.66) 23.37,49.01 23.84,48.54 P1.6
  BOTTOM w0.203: U1.13 51.53,33.43 57.4,27.55 57.4,24.26 55.88,22.73 44.45,22.73 P7.2
SPI0_SCK: length 95.5
  TOP w0.152: U1.14 53.03,33.45 53.34,33.15 58.03,33.15 58.7,33.82 58.7,35.91 55.35,39.26 55.35,52.07 52.89,54.53 32.96,54.53 30.09,51.65 25.69,51.65 23.98,49.95 v1(23.98,49.3)
  BOTTOM w0.152: P1.8 24.34,48.54 23.98,48.9 v1(23.98,49.3)
  BOTTOM w0.203: U1.14 53.03,32.57 57.91,27.68 57.91,24 56.01,22.1 46.35,22.1 P7.4
SPI0_SS0: length 79.6
  TOP w0.152: v1(26.85,49.66) 30.6,49.66 33.7,52.75 52.15,52.75 53.57,51.34 53.57,36.7 v1(54.07,36.2)
  BOTTOM w0.152: v1(26.85,49.66) P1.18
  BOTTOM w0.203: P7.6 48.26,21.46 56.07,21.46 58.34,23.74 58.34,35.89 57.73,36.5 54.89,36.5 54.58,36.2 v1(54.07,36.2)
SPI2_MISO__SPI_CFG1: length 47.6
  TOP w0.203: v1(51.31,67.44) v1(48.77,67.44) ; v1(51.4,79.58) 51.4,79.21 51.28,79.09 U8.2
  BOTTOM w0.203: v1(51.4,79.58) 52.83,78.15 52.83,68.96 v1(51.31,67.44) ; P1.32 30.35,50.02 40.62,60.29 45.19,60.29 48.77,63.86 v1(48.77,67.44)
SPI2_MOSI: length 49.2
  TOP w0.203: v1(52.07,79.88) 52.07,79.12 51.78,78.83 U8.1 ; v1(51.34,66.67) v1(48.01,66.67)
  BOTTOM w0.203: v1(52.07,79.88) 53.34,78.61 53.34,68.68 v1(51.34,66.67) ; v1(48.01,66.67) 48.01,66.17 48.26,65.91 48.26,64.06 44.98,60.79 40.41,60.79 29.85,50.22 P1.30
SPI2_SCK: length 51.7
  TOP w0.203: v1(52.83,62.87) v1(46.23,62.87) ; U8.38 55.1,76.56 v1(55.88,77.34)
  BOTTOM w0.203: v1(52.83,62.87) 53.34,62.87 56.28,65.8 56.28,75.93 55.88,76.32 v1(55.88,77.34) ; v1(46.23,62.87) 44.65,61.29 40.2,61.29 29.35,50.43 P1.28
SPI2_SS0: length 39.7
  TOP w0.203: U8.29 51.28,71.65 52.32,70.61 52.32,66.81 51.05,65.53 v1(47.5,65.53)
  BOTTOM w0.203: v1(47.5,65.53) 47.5,64.93 44.36,61.79 40,61.79 28.85,50.64 P1.26
SPI3_MISO: length 37
  TOP w0.152: v1(30.28,20.7) 28,22.99 M1.J2_6
  BOTTOM w0.152: v1(30.28,20.7) 30.28,21.78 30.48,21.97 30.48,37.3 29.85,37.93 P1.29
SPI3_MOSI: length 58
  BOTTOM w0.152: P1.31 30.35,37.93 30.84,37.44 30.84,11.92 19.96,1.04 9.24,1.04 M1.J1_3
SPI3_SCK: length 54.5
  BOTTOM w0.152: P1.25 28.85,37.92 29.59,37.18 29.59,36.06 29.36,35.83 29.36,10.95 19.81,1.4 11.43,1.4 M1.J1_4
SPI3_SDIO2: length 66
  BOTTOM w0.203: P7.17 61.72,12.57 63.25,12.57 64.26,13.59 64.26,19.94 60.78,23.42 60.78,37.71 58.51,39.98 45.76,39.98 44.3,41.44 44.3,45.12 42.4,47.02 40.61,47.02 38.17,49.45 35.86,49.45 34.85,48.44 P1.50
SPI3_SDIO3: length 71.5
  BOTTOM w0.203: P1.48 34.35,48.56 35.65,49.86 38.34,49.86 40.78,47.42 42.57,47.42 44.7,45.29 44.7,41.61 45.93,40.39 58.68,40.39 61.21,37.86 61.21,23.57 64.77,20.01 64.77,13.08 63.5,11.81 59.94,11.81 P7.15
SPI3_SS0: length 86.6
  TOP w0.152: v1(36.32,48.9) 33.76,46.33 13.17,46.33 5.33,38.49 5.33,26.28 6.34,25.27 12.7,25.27 13.97,24 13.97,20.7 15.59,19.07 15.59,4.35 16.51,3.43 16.51,2.16 15.75,1.4 13.97,1.4 M1.J1_5
  BOTTOM w0.152: v1(36.32,48.9) 36.05,48.9 35.35,48.2 P1.52
SPI3_SS1: length 84.6
  TOP w0.152: v1(36.07,51.13) 31.98,47.04 12.88,47.04 4.62,38.79 4.62,25.98 6.52,24.09 10.83,24.09 11.43,23.5 11.43,22.48 15.24,18.67 M1.J1_6
  BOTTOM w0.152: P1.44 33.35,48.94 35.54,51.13 v1(36.07,51.13)
SPI3_SS2: length 63.1
  TOP w0.152: M1.J2_5 12.7,24.09 12.02,24.77 6.34,24.77 4.98,26.13 4.98,38.64 13.03,46.69 32.79,46.69 v1(36.53,50.42)
  BOTTOM w0.152: P1.46 33.85,48.6 35.67,50.42 v1(36.53,50.42)
SPI3_SS3: length 54.2
  TOP w0.152: v1(30.23,19.69) 30.23,17.78 36.44,11.56 v1(54.36,11.56)
  BOTTOM w0.152: v1(54.36,11.56) P7.13 ; v1(30.23,19.69) 29.72,20.19 29.72,21.85 29.97,22.1 29.97,37.3 29.35,37.93 P1.27
SPI_CFG1: length 51.1
  TOP w0.203: v1(56.9,77.34) 55.61,76.06 U8.37 ; v1(53.59,62.1) v1(48.51,62.1)
  BOTTOM w0.203: P1.36 31.35,49.6 41.03,59.29 45.7,59.29 v1(48.51,62.1) ; v1(53.59,62.1) 56.9,65.41 v1(56.9,77.34)
SPIXR_SCK: length 99.9
  TOP w0.152: P7.9 51.82,12.32 63.06,12.32 64.41,13.67 64.41,21.63 59.94,26.1 59.94,36.7 56.49,40.16 56.49,52.51 53.41,55.6 32.52,55.6 29.64,52.72 24.79,52.72 22.1,50.03 v1(22.1,48.39)
  BOTTOM w0.152: v1(22.1,48.39) 22.56,48.39 22.84,48.11 P1.2
SPIXR_SDIO0: length 94.8
  TOP w0.152: v1(22.73,49.15) 22.73,50.16 24.93,52.37 29.79,52.37 32.67,55.24 53.22,55.24 56.08,52.38 56.08,39.8 59.44,36.45 59.44,26.03 64.01,21.46 64.01,13.84 62.99,12.83 53.85,12.83 P7.11
  BOTTOM w0.152: v1(22.73,49.15) 23.34,48.54 P1.4
SPIXR_SDIO1: length 54.9
  BOTTOM w0.203: P7.19 63.75,16.63 63.75,18.54 59.97,22.33 59.97,37.38 58.18,39.17 45.42,39.17 43.48,41.1 43.48,44.78 42.15,46.11 37.25,46.11 36.85,46.51 P1.58
SWPD_EN: length 45.7
  TOP w0.203: U8.33 53.1,74.06 53.65,73.5 53.65,64.96 52.12,63.42 v1(43.84,63.42)
  BOTTOM w0.203: v1(43.84,63.42) 39.51,63.42 27.4,51.32 27.4,49.43 27.35,49.37 P1.20
TS_CAPT: length 44.2
  TOP w0.203: v1(54.1,77.34) 53.54,77.34 53.33,77.56 U8.40
  BOTTOM w0.203: v1(54.1,77.34) 54.1,74.54 55.07,73.58 55.07,66.12 46.74,57.79 41.66,57.79 32.85,48.98 P1.42
TS_TIMER__MS_SEL: length 37.7
  TOP w0.203: v1(49.78,64.77) 51.18,64.77 52.83,66.42 52.83,70.86 51.78,71.91 U8.30
  BOTTOM w0.203: P1.38 31.85,49.39 41.24,58.79 46.21,58.79 49.78,62.36 v1(49.78,64.77)
TX2P4_EN: length 43.2
  TOP w0.203: U8.31 53.14,73.06 53.25,72.95 53.25,65.57 51.82,64.14 v1(45.34,64.14)
  BOTTOM w0.203: v1(45.34,64.14) 44,62.79 39.58,62.79 27.85,51.05 P1.22
TXD_485: length 24.3
  TOP w0.152: v1(23.37,54.1) 21.34,52.07 21.34,49.15 v1(20.57,48.39)
  BOTTOM w0.152: P1.3 23.34,40.23 22.45,39.34 19.45,39.34 18.64,40.15 18.64,46.46 v1(20.57,48.39) ; v1(23.37,54.1) U2.7
TXEV: length 54.9
  BOTTOM w0.203: P7.12 54.1,19.69 56.65,19.69 59.56,22.59 59.56,37.21 58.01,38.76 45.25,38.76 43.08,40.94 43.08,44.61 41.99,45.71 36.82,45.71 36.35,46.18 P1.56
TXN: length 6.1
  TOP w0.203: R24.1 40.82,77.43 R26.2 43.85,77.43 44.22,77.06 U8.12
TXP: length 8.2
  TOP w0.203: U8.15 45.21,75.56 44.7,75.06 44.7,73.28 44.11,72.68 R21.2 40.76,72.68 R22.1
UART2_CTS: length 21.9
  BOTTOM w0.152: P6.1 39.12,27.05 38.76,27.41 34.21,27.41 31.19,30.42 31.19,37.59 30.85,37.93 P1.33
UART2_PPS: length 31.1
  BOTTOM w0.152: P1.41 32.85,39.32 32.46,38.93 32.46,38.33 32.61,38.18 32.61,31.01 34.8,28.83 48.77,28.83 49.28,28.32 P6.5
UART2_RTS: length 24.2
  BOTTOM w0.152: P6.2 41.66,27.43 41.32,27.76 34.36,27.76 31.55,30.57 31.55,37.74 31.35,37.94 P1.35
UART2_RX: length 26.5
  BOTTOM w0.152: P6.3 44.2,27.81 43.89,28.12 34.5,28.12 31.9,30.72 31.9,37.89 31.75,38.04 31.75,39.23 31.85,39.32 P1.37
UART2_TX: length 28.9
  BOTTOM w0.152: P6.4 46.74,28.19 46.45,28.47 34.65,28.47 32.26,30.87 32.26,38.03 32.11,38.18 32.11,39.08 32.35,39.32 P1.39
UNNAMED_4_CN3P_I274_N3: length 4.2
  BOTTOM w0.305: R3.1 2.87,59.4 3.77,60.3 P5.3
UNNAMED_4_DIOLED_I203_P: length 2.8
  TOP w0.152: DS1.A 72.91,32.33 R8.2
UNNAMED_4_DIOLED_I206_P: length 2.8
  TOP w0.152: DS2.A 72.92,27.74 R9.2
UNNAMED_4_DIOLED_I281_P: length 2.8
  TOP w0.152: DS4.A 72.9,36.93 R6.2
UNNAMED_4_DIOLED_I283_P: length 2.8
  TOP w0.152: R4.2 DS3.A
UNNAMED_9_ADIN1110V2_I109_CEXT2: length 2.8
  TOP w0.203: U8.19 45.75,73.56 v1(45.47,73.28)
  BOTTOM w0.203: v1(45.47,73.28) 44.83,72.64 44.83,72.39 C52.1
UNNAMED_9_ADIN1110V2_I109_CEXT3: length 3.9
  TOP w0.203: U8.20 46.26,73.06 45.97,72.77 v1(45.97,72.14)
  BOTTOM w0.203: C53.1 45.72,70.61 45.97,70.86 v1(45.97,72.14)
UNNAMED_9_ADIN1110V2_I109_LED0: length 3.1
  TOP w0.203: U8.3 50.78,79.86 R102.2
UNNAMED_9_ADIN1110V2_I109_LED1: length 7
  TOP w0.203: U8.6 49.28,79.08 49.22,79.14 49.22,80.08 50.29,81.15 50.55,81.15 R105.2 R104.2
UNNAMED_9_ADIN1110V2_I109_TEST1: length 2.3
  TOP w0.203: R35.1 50.62,71.1 49.78,71.94 U8.26
UNNAMED_9_CAP_I111_N1: length 2.1
  BOTTOM w0.305: C33.1 44.03,36.57 U1.8
UNNAMED_9_CAP_I111_N2: length 2.1
  BOTTOM w0.305: C33.2 45.53,36.47 U1.9
